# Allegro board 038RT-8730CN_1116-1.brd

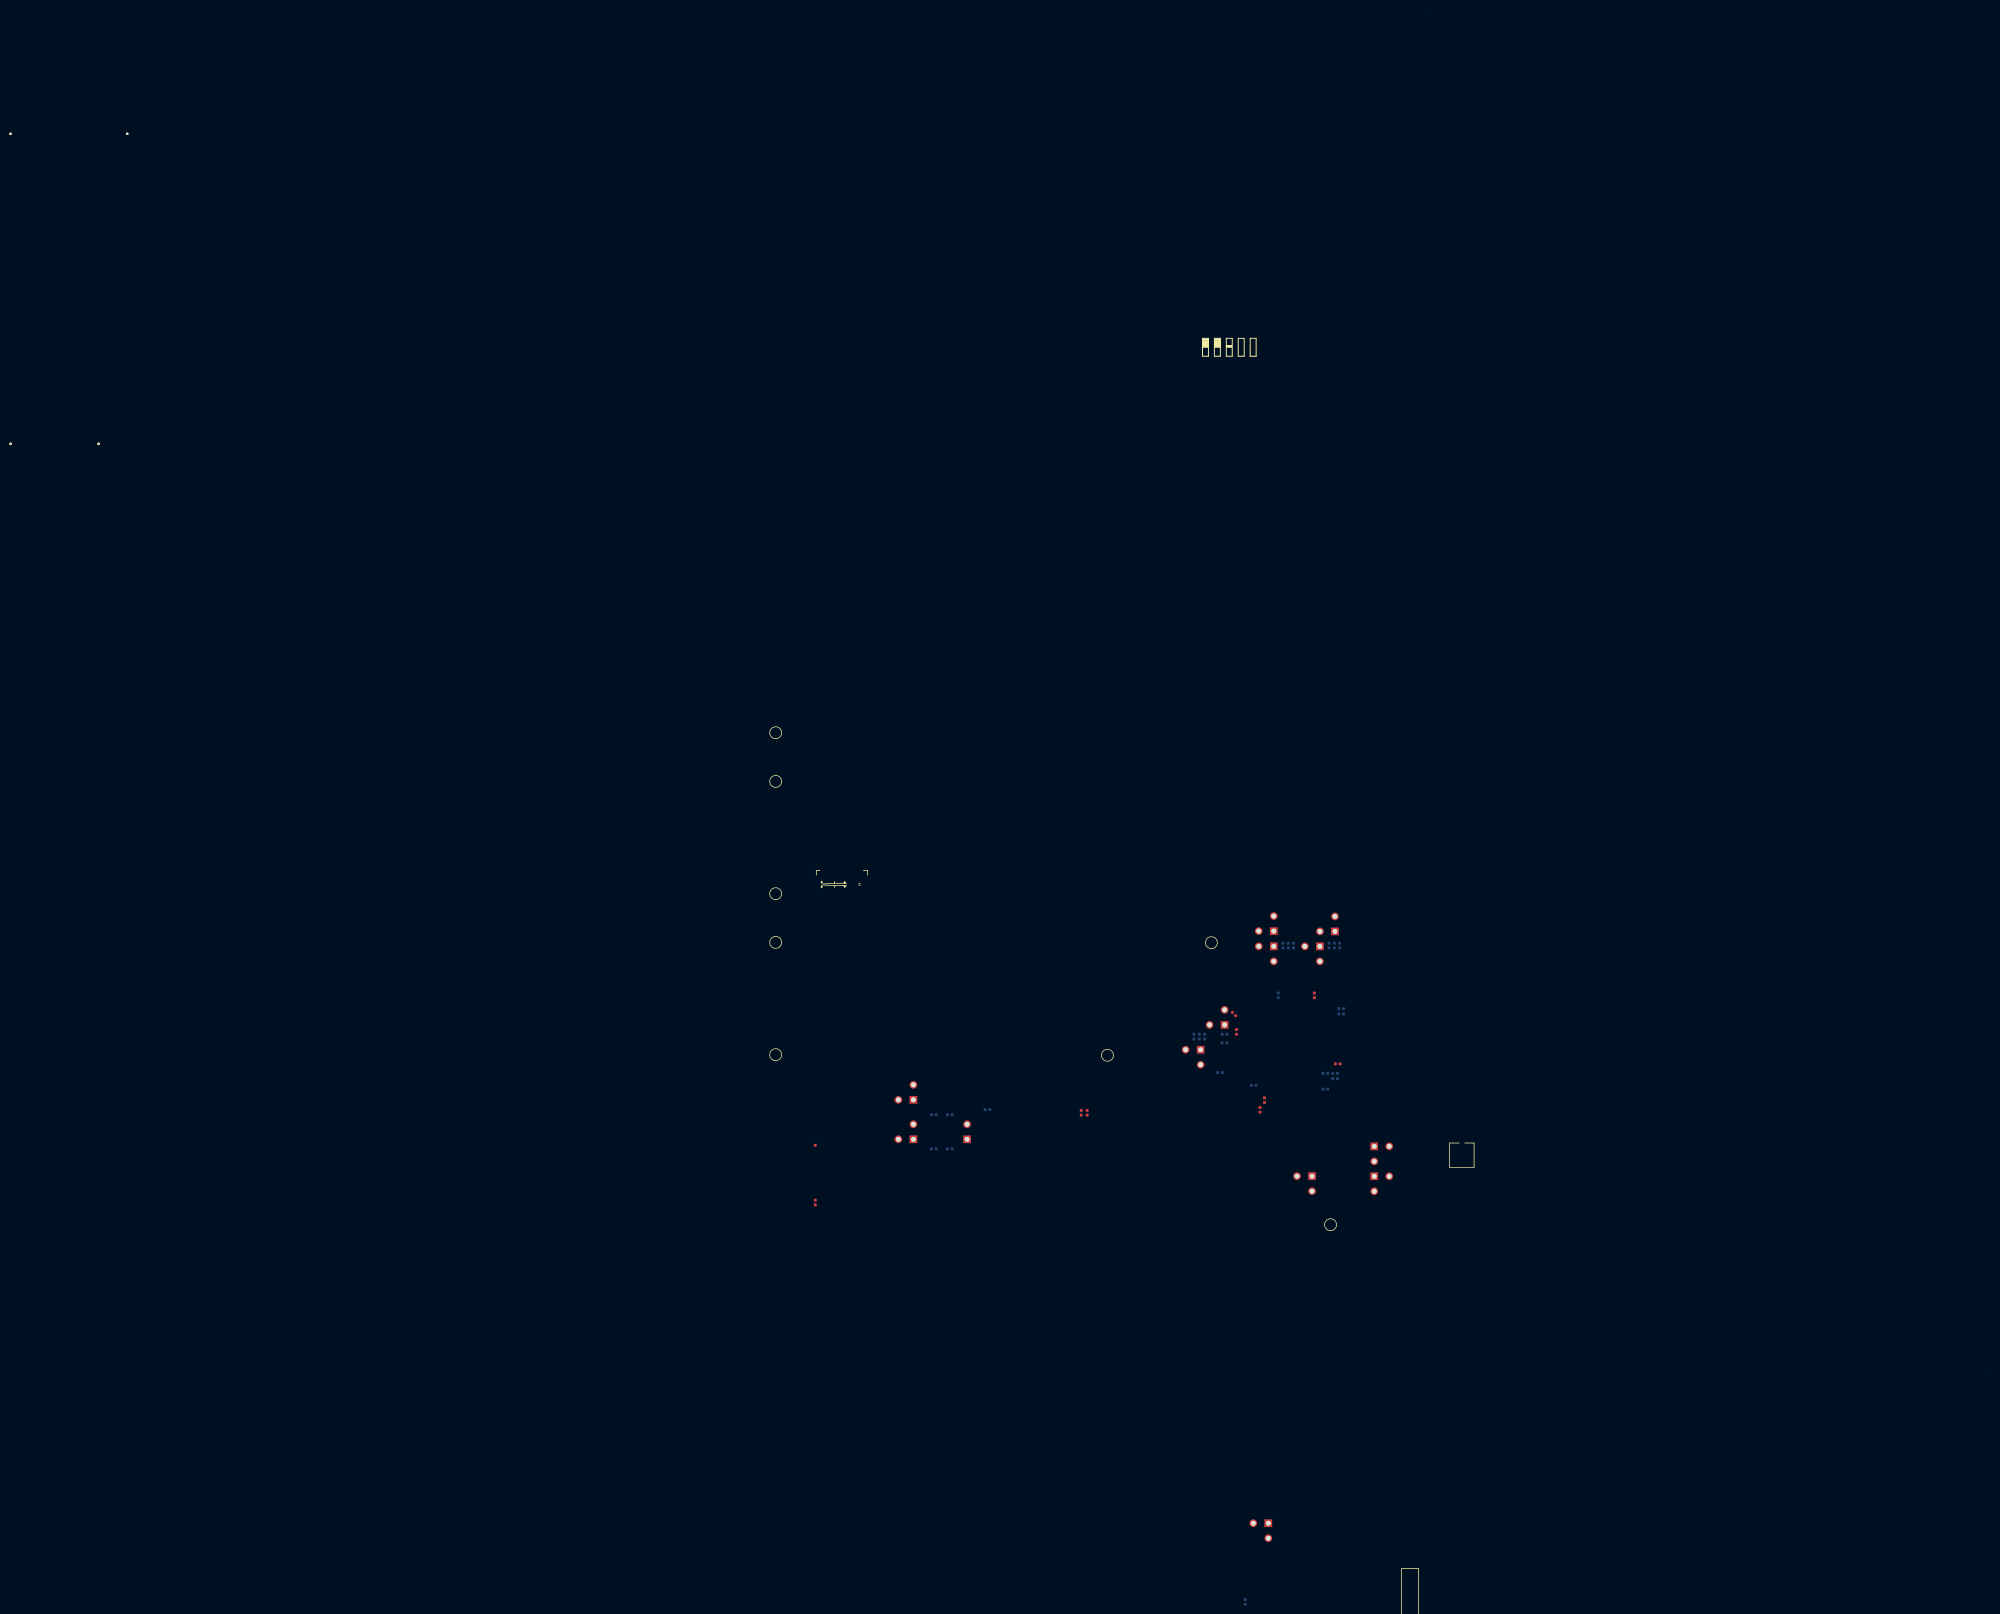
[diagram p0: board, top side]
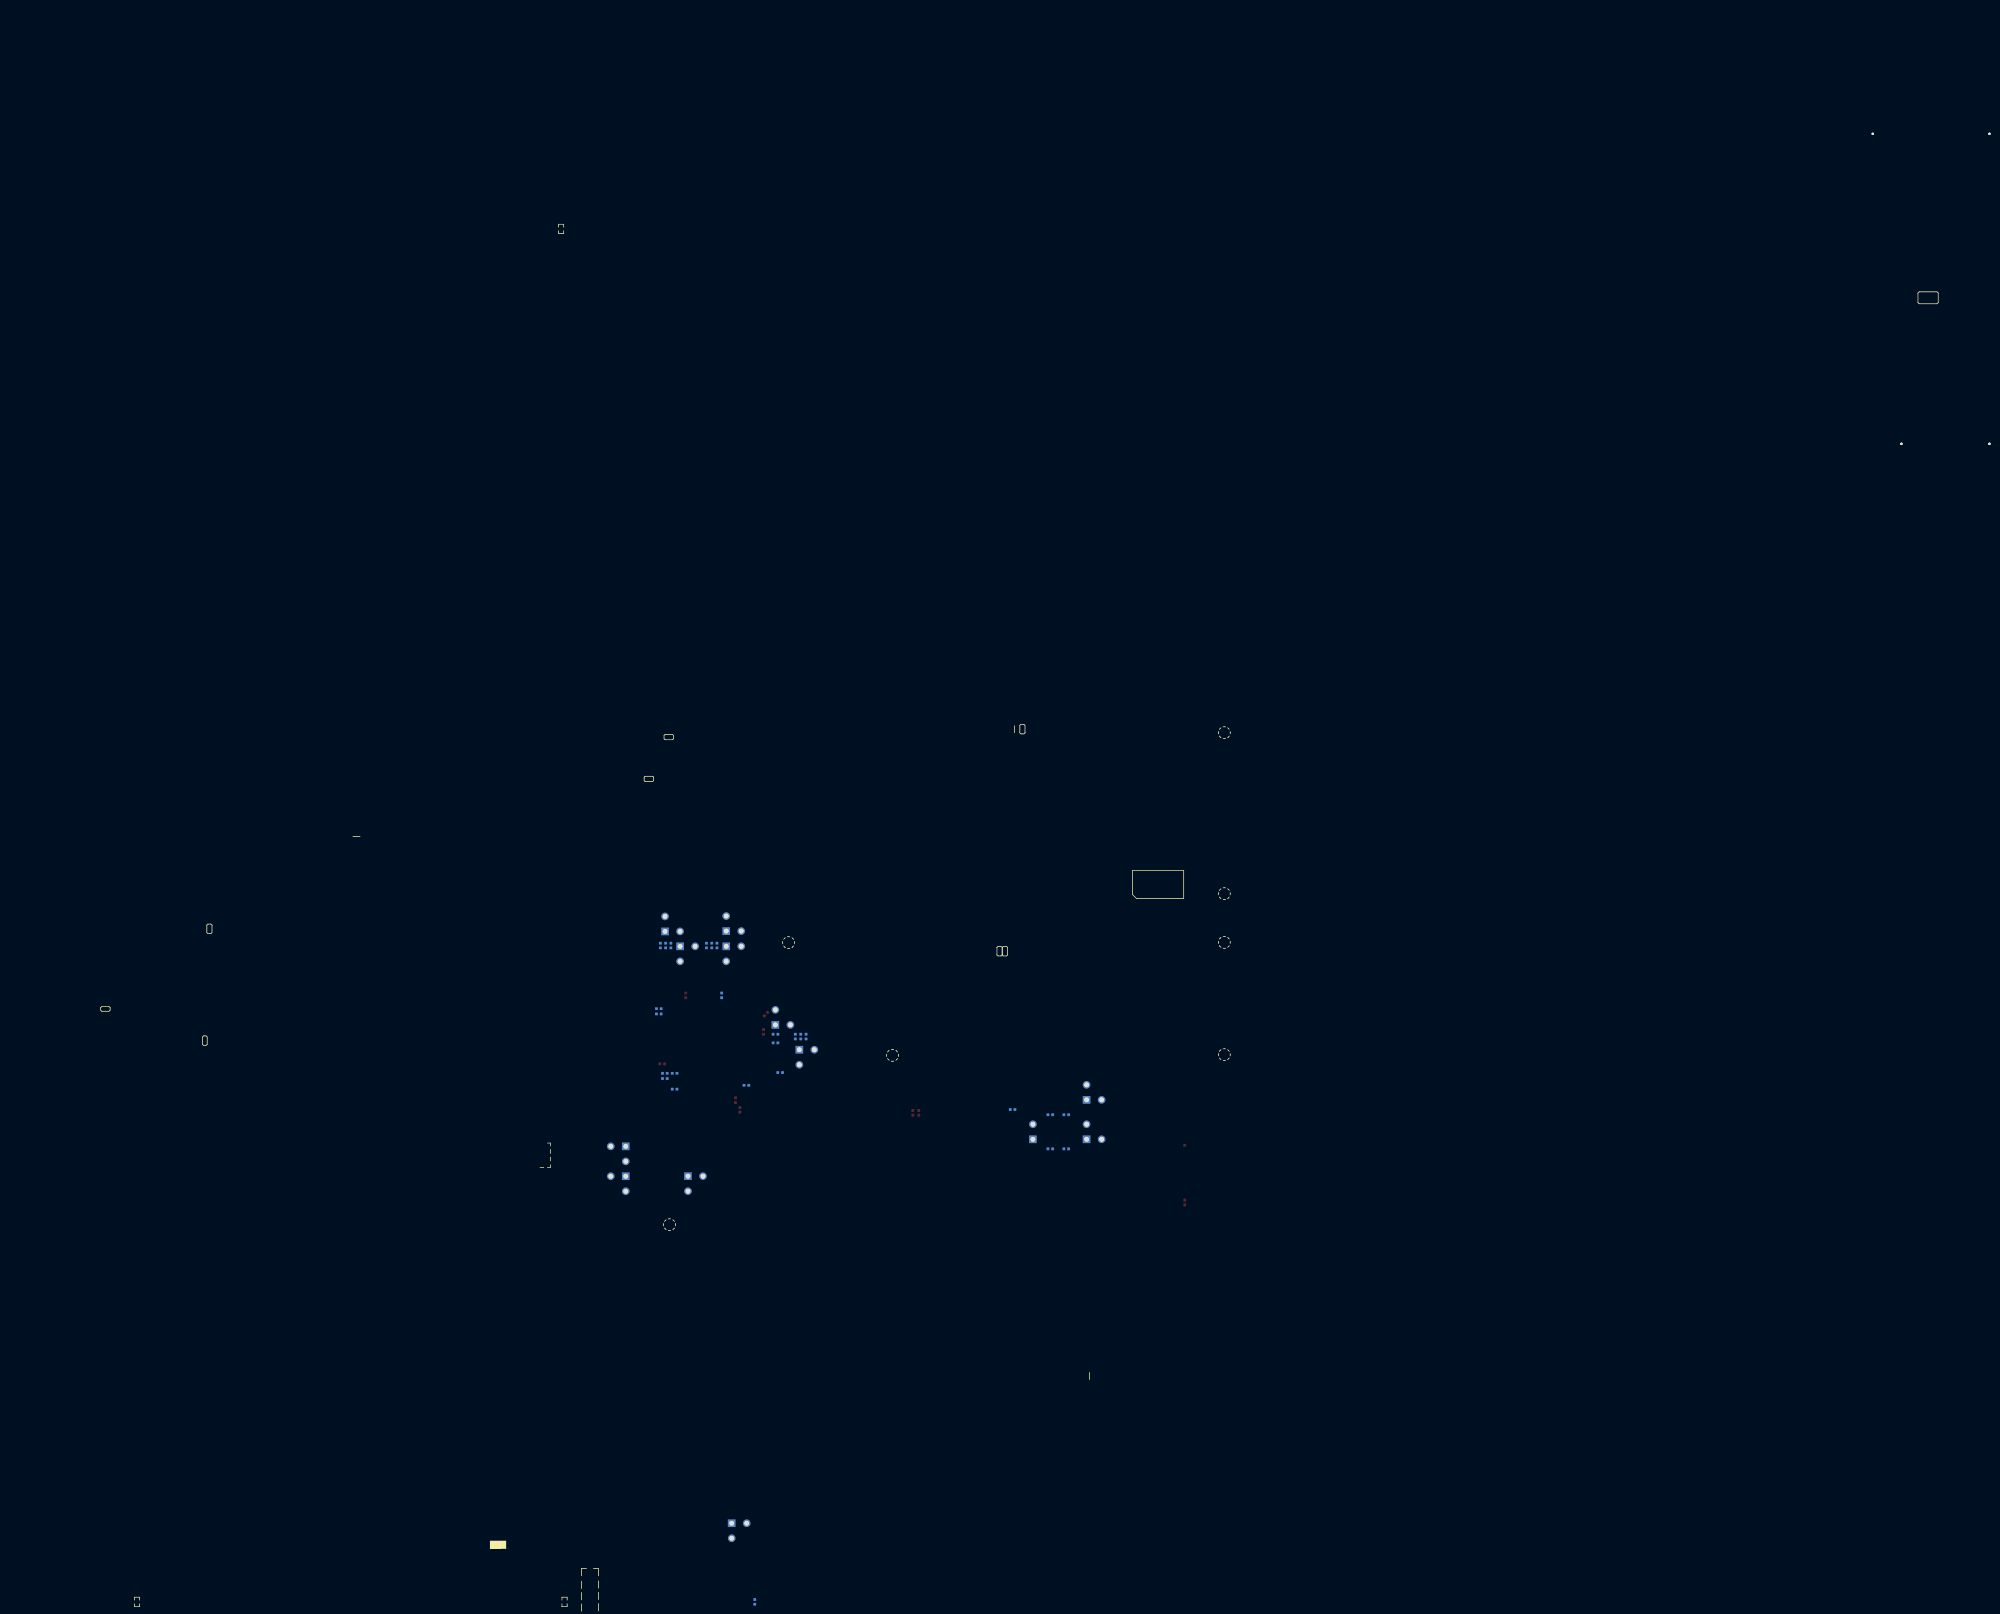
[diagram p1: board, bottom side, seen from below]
No outline. copper layers: Top, Bottom. Coordinates in mm from the lowest, leftmost part position.

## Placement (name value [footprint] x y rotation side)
1BD1  BD120-1.5A-S4-MU  [FB0402]  339.97 257.1 270 bottom
1BD2  BD120-1.5A-S4-MU  [FB0402]  355.74 254.24 180 bottom
1BD3  BD120-1.5A-S4-MU  [FB0402]  338.93 257.1 270 bottom
1BD5  BD120-1.5A-S4-MU  [FB0402]  336.11 247.53 0 bottom
1BD7  BD120-1.5A-S4-MU  [FB0402]  341.01 257.1 270 bottom
1BD9  BD120-1.5A-S4-MU  [FB0402]  359.98 244.31 180 bottom
1BD11  BD120-1.5A-S4-MU  [FB0402]  355.74 253.2 180 bottom
1BD12  BD120-1.5A-S4-MU  [FB0402]  347.85 257.1 270 bottom
1BD13  BD120-1.5A-S4-MU  [FB0402]  336.14 240.68 0 bottom
1BD15  BD120-1.5A-S4-MU  [FB0402]  339.26 236.89 0 bottom
1BD16  BD120-1.5A-S4-MU  [FB0402]  342.57 243.52 180 bottom
1BD17  BD120-1.5A-S4-MU  [FB0402]  342.57 242.48 180 bottom
1BD18  BD120-1.5A-S4-MU  [FB0402]  354.49 239.43 180 bottom
1BD19  BD120-1.5A-S4-MU  [FB0402]  354.49 238.23 180 bottom
1BD20  BD120-1.5A-S4-MU  [FB0402]  334.56 247.48 270 bottom
1BD21  BD120-1.5A-S4-MU  [FB0402]  354.49 236.09 180 bottom
1BD22  BD120-1.5A-S4-MU  [FB0402]  341.08 233.24 180 bottom
1BD23  BD120-1.5A-S4-MU  [FB0402]  341.08 235.3 0 bottom
1BD27  NC/BD120-1.5A-S4-MU  [FB0402]  242.51 266.02 180 bottom
1BD28  BD120-1.5A-S4-MU  [FB0402]  335.59 250.31 270 bottom
1BD29  BD120-1.5A-S4-MU  [FB0402]  345.59 257.1 270 bottom
1BD30  BD120-1.5A-S4-MU  [FB0402]  335.74 253.12 225 bottom
1BD31  BD120-1.5A-S4-MU  [FB0402]  352.63 256.63 180 bottom
1BD32  BD120-1.5A-S4-MU  [FB0402]  265.06 266.44 270 top
1BD33  BD120-1.5A-S4-MU  [FB0402]  339.05 127.89 270 bottom
1BD34  BD120-1.5A-S4-MU  [FB0402]  342.26 231.51 0 bottom
1BD35  BD120-1.5A-S4-MU  [FB0402]  352.4 236.09 180 bottom
1BD36  BD120-1.5A-S4-MU  [FB0402]  334.09 240.69 0 bottom
1BD37  BD120-1.5A-S4-MU  [FB0402]  349.98 257.1 270 bottom
1C1  NC/1P-25-N-S2-WA  [C0201]  347.94 238.42 45 top
1C2  10P-50-N-S2-MU  [C0201]  352.27 233.44 300 top
1C3  NC/1.2P-50-N-S2-MU  [C0201]  349.75 237.46 45 top
1C4  NC/1P-25-N-S2-WA  [C0201]  346.58 238.11 225 top
1C5  NC/1.2P-50-N-S2-MU  [C0201]  347.55 236.29 225 top
1C6  10P-50-N-S2-MU  [C0201]  349.44 232.63 90 top
1C7  NC/10P-50-N-S2-MU  [C0201]  349.14 232.33 180 top
1C8  CNC-S2  [C0201]  349.14 227.46 180 top
1C9  NC/1P-25-N-S2-WA  [C0201]  345.65 237.58 180 bottom
1C10  NC/1.2P-50-N-S2-MU  [C0201]  345.05 235.61 180 bottom
1C11  NC/1P-25-N-S2-WA  [C0201]  343.88 238.23 180 top
1C12  NC/1.2P-50-N-S2-MU  [C0201]  343.28 236.26 180 top
1C13  10P-50-N-S2-MU  [C0201]  343.58 228.62 90 top
1C14  NC/10P-50-N-S2-MU  [C0201]  343.88 228.32 0 top
1C15  CNC-S2  [C0201]  343.88 226.5 0 top
1C16  NC/1P-25-N-S2-WA  [C0201]  343.88 238.23 180 bottom
1C17  NC/0.1U-35-X-S2-MU  [C0201]  352.4 242.06 180 bottom
1C18  NC/0.1U-35-X-S2-MU  [C0201]  352.4 241.21 180 bottom
1C19  NC/1.2P-50-N-S2-MU  [C0201]  343.28 236.26 180 bottom
1C20  0.1U-35-X-S2-MU  [C0201]  352.4 238.98 0 bottom
1C21  0.1U-35-X-S2-MU  [C0201]  352.4 239.83 0 bottom
1C22  0.1U-16-X-S4-MU  [C0402]  262.52 266.41 90 top
1C23  0.9P-50-N-S4-MU  [C0402]  335.37 245.27 270 top
1C24  0.1U-25-X-S4-TY  [C0402]  242.54 267.1 0 bottom
1C25  0.9P-50-N-S4-MU  [C0402]  335.37 242.5 90 top
1C38  1P-50-N-S4-WA  [C0402]  234.52 258.72 0 bottom
1C39  22P-50-N-S4-AVX  [C0402]  231.12 258.72 0 bottom
1C40  1P-50-N-S4-WA  [C0402]  234.52 265.99 0 bottom
1C41  22P-50-N-S4-AVX  [C0402]  231.12 265.99 0 bottom
1C44  0.1U-35-X-S2-MU  [C0201]  342.71 247.36 0 bottom
1C45  0.1U-35-X-S2-MU  [C0201]  351.18 251.27 270 bottom
1C46  0.1U-35-X-S2-MU  [C0201]  342.71 246.51 0 bottom
1C47  0.1U-35-X-S2-MU  [C0201]  351.41 244.05 180 bottom
1C48  0.1U-35-X-S2-MU  [C0201]  338.55 244.6 180 top
1C49  0.1U-35-X-S2-MU  [C0201]  351.41 247.77 180 bottom
1C52  0.1U-35-X-S2-MU  [C0201]  342.71 248.21 0 bottom
1C53  10U-10-X-S4-SS  [C0402]  326.53 248.35 90 bottom
1C54  0.1U-35-X-S2-MU  [C0201]  347.6 251.27 270 bottom
1C55  0.1U-25-X-S4-TY  [C0402]  328.8 248.35 90 bottom
1C56  0.1U-35-X-S2-MU  [C0201]  355.52 245.28 0 top
1C57  NC/10U-10-X-S4-SS  [C0402]  327.66 248.35 90 bottom
1C58  0.1U-35-X-S2-MU  [C0201]  342.44 255.8 90 top
1C59  0.1U-35-X-S2-MU  [C0201]  351.4 249.26 180 bottom
1C60  10U-10-X-S4-SS  [C0402]  357.88 254.29 0 bottom
1C61  0.1U-35-X-S2-MU  [C0201]  346.65 251.26 270 bottom
1C62  22U-25-X-S8-MU  [C0805]  326.41 256.59 0 bottom
1C63  22U-25-X-S8-MU  [C0805]  326.41 258.62 0 bottom
1C64  0.1U-35-X-S2-MU  [C0201]  338.55 242.47 180 top
1C65  47U-16-T-SC  [CODE_C]  259.93 272.36 180 bottom
1C66  10U-16-T-SA  [CODE_A]  259.97 272.36 180 top
1C67  10U-10-X-S4-SS  [C0402]  357.88 253.17 0 bottom
1C68  22U-10-T-SA  [CODE_A]  357.27 210.88 0 bottom
1C69  22U-10-T-SA  [CODE_A]  357.27 213.47 0 bottom
1C70  22U-10-T-SA  [CODE_A]  357.27 216.04 0 bottom
1C71  22U-10-T-SA  [CODE_A]  357.27 213.47 0 top
1C72  22U-10-T-SA  [CODE_A]  357.27 210.88 0 top
1C73  10U-10-X-S4-SS  [C0402]  334.06 239.62 180 bottom
1C74  0.1U-35-X-S2-MU  [C0201]  345.35 242.65 90 bottom
1C75  0.1U-35-X-S2-MU  [C0201]  355.52 242.53 0 top
1C76  10U-10-X-S4-SS  [C0402]  339.23 237.96 180 bottom
1C77  0.1U-35-X-S2-MU  [C0201]  344.54 242.65 90 bottom
1C78  0.1U-35-X-S2-MU  [C0201]  338.55 243.15 180 top
1C79  0.1U-35-X-S2-MU  [C0201]  338.55 241.78 180 top
1C83  10U-10-X-S4-SS  [C0402]  354.52 240.52 0 bottom
1C84  0.1U-35-X-S2-MU  [C0201]  346.87 242.65 90 bottom
1C85  0.1U-35-X-S2-MU  [C0201]  346.14 242.65 90 bottom
1C88  0.1U-35-X-S2-MU  [C0201]  338.55 245.26 180 top
1C89  10U-10-X-S4-SS  [C0402]  333.03 248.85 180 bottom
1C90  10U-10-X-S4-SS  [C0402]  354.52 237.15 0 bottom
1C91  0.1U-35-X-S2-MU  [C0201]  346.46 239.87 0 bottom
1C92  22U-25-X-S8-MU  [C0805]  366.24 212.93 180 bottom
1C93  22U-25-X-S8-MU  [C0805]  366.24 212.93 180 top
1C94  47U-16-T-SC  [CODE_C]  365.79 209.62 180 bottom
1C95  10U-16-T-SA  [CODE_A]  365.79 209.62 180 top
1C96  10U-10-X-S4-SS  [C0402]  356.6 240.52 0 bottom
1C97  10U-10-X-S4-SS  [C0402]  340.61 232.74 270 top
1C98  0.1U-35-X-S2-MU  [C0201]  339.67 233.64 270 top
1C99  10U-10-X-S4-SS  [C0402]  341.55 234.8 270 top
1C100  0.1U-35-X-S2-MU  [C0201]  341.83 237.95 270 top
1C101  10U-10-X-S4-SS  [C0402]  333.03 247.01 180 bottom
1C102  0.1U-35-X-S2-MU  [C0201]  351.41 245.56 180 bottom
1C105  0.1U-35-X-S2-MU  [C0201]  351.4 246.35 180 bottom
1C106  10U-10-X-S4-SS  [C0402]  356.43 267.74 90 bottom
1C107  0.1U-35-X-S2-MU  [C0201]  355.52 246.65 0 top
1C108  0.1U-25-X-S4-TY  [C0402]  355.31 267.74 90 bottom
1C109  NC/10U-10-X-S4-SS  [C0402]  357.55 267.74 90 bottom
1C110  1U-10-X-S4-MU  [C0402]  357.14 242.53 180 top
1C111  10U-10-X-S4-SS  [C0402]  335.59 249.34 270 top
1C112  0.1U-35-X-S2-MU  [C0201]  337.6 250.06 270 top
1C113  10U-25-X-S6-MU  [C0603]  361.74 247.85 90 bottom
1C116  22U-25-X-S8-MU  [C0805]  346.8 259.97 180 bottom
1C117  22U-25-X-S8-MU  [C0805]  346.8 262.13 180 bottom
1C118  10U-10-X-S4-SS  [C0402]  344.5 257.13 90 bottom
1C119  0.1U-35-X-S2-MU  [C0201]  345.72 251.26 270 bottom
1C120  47U-16-T-SC  [CODE_C]  280.47 270.61 270 bottom
1C121  10U-16-T-SA  [CODE_A]  280.47 270.61 270 top
1C122  10U-10-X-S4-SS  [C0402]  356.6 239.41 0 bottom
1C123  10U-10-X-S4-SS  [C0402]  335.05 253.14 135 top
1C124  0.1U-35-X-S2-MU  [C0201]  338.55 251.94 180 top
1C125  10U-10-X-S4-SS  [C0402]  352.16 257.13 90 top
1C126  0.1U-35-X-S2-MU  [C0201]  352.11 255.75 180 top
1C127  10U-10-X-S4-SS  [C0402]  263.79 266.41 90 top
1C128  0.1U-35-X-S2-MU  [C0201]  261.25 266.41 90 top
1C129  10U-10-X-S4-SS  [C0402]  332.04 240.68 180 bottom
1C130  0.1U-25-X-S4-TY  [C0402]  337.96 127.92 90 bottom
1C131  22U-10-T-SA  [CODE_A]  343.5 130.48 0 bottom
1C132  22U-10-T-SA  [CODE_A]  343.5 125.35 0 top
1C133  22U-10-T-SA  [CODE_A]  343.5 127.92 0 top
1C134  22U-10-T-SA  [CODE_A]  343.5 127.92 0 bottom
1C135  22U-10-T-SA  [CODE_A]  343.5 125.35 0 bottom
1C136  10U-10-X-S4-SS  [C0402]  346.61 267.74 90 bottom
1C137  0.1U-25-X-S4-TY  [C0402]  345.5 267.74 90 bottom
1C138  NC/10U-10-X-S4-SS  [C0402]  347.73 267.74 90 bottom
1C139  22U-25-X-S8-MU  [C0805]  335.27 267.42 270 bottom
1C140  47U-16-T-SC  [CODE_C]  285.09 270.61 270 bottom
1C141  10U-16-T-SA  [CODE_A]  285.09 270.61 270 top
1C142  22U-25-X-S8-MU  [C0805]  337.56 267.42 270 bottom
1C143  NC/10P-50-N-S4-WA  [C0402]  355.78 250.66 180 bottom
1C144  NC/10P-50-N-S4-WA  [C0402]  355.78 249.49 180 bottom
1C145  NC/10P-50-N-S4-WA  [C0402]  205.88 251.35 90 top
1C146  NC/10P-50-N-S4-WA  [C0402]  205.88 254.55 90 top
1C147  NC/10P-50-N-S4-WA  [C0402]  205.88 244.08 90 top
1C148  NC/10P-50-N-S4-WA  [C0402]  205.88 247.28 90 top
1C149  NC/10P-50-N-S4-WA  [C0402]  205.88 259.98 90 top
1C150  NC/10P-50-N-S4-WA  [C0402]  205.88 263.18 90 top
1C152  0.1U-35-X-S2-MU  [C0201]  348.44 251.27 270 bottom
1C153  CNC-S2  [C0201]  350.9 247.1 180 bottom
1D1  RCLAMP3321P-SLP1006P2  [DIODE_1X0P6MM]  352.51 232.17 30 top
1D2  RCLAMP3321P-SLP1006P2  [DIODE_1X0P6MM]  349.02 228.35 0 top
1D3  RCLAMP3321P-SLP1006P2  [DIODE_1X0P6MM]  344 227.38 180 top
1J1  HDR-4X1-F-1  [CONN_4X1_2P54MM_FL10P5MM]  213.31 267.71 270 top
1J2  HDR-4X1-F-1  [CONN_4X1_2P54MM_FL10P5MM]  332.56 125.38 270 top
1J3  HDR-4X1-F-1  [CONN_4X1_2P54MM_FL10P5MM]  207.08 267.71 270 top
1J4  HDR-8X1-M  [JP_8P_100]  216.58 178.6 270 top
1J5  HDR-1X1-M  [JP_1P_RD070_040]  347.48 133.26 90 top
1J6  HDR-2X1-M  [JP_2P_100]  344.57 133.26 90 top
1J7  HDR-2X1-M  [JP_2P_100]  321.46 157.26 0 top
1J8  HDR-2X1-M  [JP_2P_100]  317.65 157.26 0 top
1J9  HDR-2X1-M  [JP_2P_100]  325.27 157.26 0 top
1K1  CU/UA2-12NJ-A-V2  [RL_NECUA2_12V_V2]  272.11 262.91 0 bottom
1K2  CU/UA2-12NJ-A-V2  [RL_NECUA2_12V_V2]  272.11 255.9 0 bottom
1K3  CU/UA2-12NJ-A-V2  [RL_NECUA2_12V_V2]  272.11 248.89 0 bottom
1K4  CU/UA2-12NJ-A-V2  [RL_NECUA2_12V_V2]  223.19 270.76 0 bottom
1K5  CU/UA2-12NJ-A-V2  [RL_NECUA2_12V_V2]  364.28 270.8 270 bottom
1K6  CU/UA2-12NJ-A-V2  [RL_NECUA2_12V_V2]  341.27 141.08 90 bottom
1K7  CU/UA2-12NJ-A-V2  [RL_NECUA2_12V_V2]  272.41 272.41 270 bottom
1K8  CU/UA2-12NJ-A-V2  [RL_NECUA2_12V_V2]  223.19 262.36 0 bottom
1K9  CU/UA2-12NJ-A-V2  [RL_NECUA2_12V_V2]  368.52 223.36 180 bottom
1K10  CU/UA2-12NJ-A-V2  [RL_NECUA2_12V_V2]  249.02 253.72 0 bottom
1K11  CU/UA2-12NJ-A-V2  [RL_NECUA2_12V_V2]  223.19 246.46 0 bottom
1K12  CU/UA2-12NJ-A-V2  [RL_NECUA2_12V_V2]  234.62 253.72 0 bottom
1K13  CU/UA2-12NJ-A-V2  [RL_NECUA2_12V_V2]  223.19 253.72 0 bottom
1K14  CU/UA2-12NJ-A-V2  [RL_NECUA2_12V_V2]  249.02 246.46 0 bottom
1K15  CU/UA2-12NJ-A-V2  [RL_NECUA2_12V_V2]  234.62 246.46 0 bottom
1K16  CU/UA2-12NJ-A-V2  [RL_NECUA2_12V_V2]  246.05 270.76 0 bottom
1K18  CU/UA2-12NJ-A-V2  [RL_NECUA2_12V_V2]  246.05 262.36 0 bottom
1K19  CU/UA2-12NJ-A-V2  [RL_NECUA2_12V_V2]  234.62 262.36 0 bottom
1K20  CU/UA2-12NJ-A-V2  [RL_NECUA2_12V_V2]  341.93 263.97 90 bottom
1K21  CU/UA2-12NJ-A-V2  [RL_NECUA2_12V_V2]  329.46 252.44 0 bottom
1K22  CU/UA2-12NJ-A-V2  [RL_NECUA2_12V_V2]  326.35 241.95 90 bottom
1K23  CU/UA2-12NJ-A-V2  [RL_NECUA2_12V_V2]  350.07 215.01 90 bottom
1K25  CU/UA2-12NJ-A-V2  [RL_NECUA2_12V_V2]  339.93 272.42 0 bottom
1K26  CU/UA2-12NJ-A-V2  [RL_NECUA2_12V_V2]  368.52 217 180 bottom
1K28  CU/UA2-12NJ-A-V2  [RL_NECUA2_12V_V2]  352.96 272.35 0 bottom
1K29  CU/UA2-12NJ-A-V2  [RL_NECUA2_12V_V2]  351.74 263.97 90 bottom
1K30  CU/UA2-12NJ-A-V2  [RL_NECUA2_12V_V2]  202.41 270.96 270 bottom
1K31  CU/UA2-12NJ-A-V2  [RL_NECUA2_12V_V2]  202.41 259.53 270 bottom
1K32  CU/UA2-12NJ-A-V2  [RL_NECUA2_12V_V2]  202.41 248.1 270 bottom
1K34  CU/UA2-12NJ-A-V2  [RL_NECUA2_12V_V2]  211.76 253.72 0 bottom
1K35  CU/UA2-12NJ-A-V2  [RL_NECUA2_12V_V2]  211.76 246.46 0 bottom
1K36  CU/UA2-12NJ-A-V2  [RL_NECUA2_12V_V2]  211.76 262.36 0 bottom
1K39  CU/UA2-12NJ-A-V2  [RL_NECUA2_12V_V2]  334.31 141.08 90 bottom
1L1  L2.2U-1.15A-S2.0X1.6-CT  [IND_201610]  330.75 247.9 270 bottom
1L3  L2.2U-1.15A-S2.0X1.6-CT  [IND_201610]  356.06 265.2 90 bottom
1L4  L2.2U-1.15A-S2.0X1.6-CT  [IND_201610]  346.25 265.2 90 bottom
1R1  0-5-S2  [R0201]  348.84 237.94 315 top
1R2  0-5-S2  [R0201]  347.06 237.2 315 top
1R3  0-5-S2  [R0201]  349.44 233.91 270 top
1R4  NC/0-5-S2  [R0201]  349.14 234.21 0 top
1R5  0-5-S2  [R0201]  345.35 236.59 270 bottom
1R6  0-5-S2  [R0201]  343.58 237.25 270 top
1R7  0-5-S2  [R0201]  343.58 229.9 270 top
1R8  NC/0-5-S2  [R0201]  343.88 230.2 180 top
1R9  0-5-S2  [R0201]  343.58 237.25 270 bottom
1R10  0-5-S4  [R0402]  262.37 246.99 90 top
1R11  0-5-S4  [R0402]  261.1 246.99 90 top
1R12  NC/10K-1-S4  [R0402]  258.46 266.41 90 top
1R13  0-5-S4  [R0402]  259.73 266.41 90 top
1R14  NC/10K-1-S4  [R0402]  259.83 246.99 90 top
1R15  0-5-S4  [R0402]  257.19 266.41 90 top
1R16  0-5-S4  [R0402]  258.56 246.99 90 top
1R17  0-5-S4  [R0402]  255.92 266.41 90 top
1R18  NC/10K-1-S4  [R0402]  257.44 246.99 90 top
1R19  0-5-S4  [R0402]  215.75 267.71 180 bottom
1R20  0-5-S4  [R0402]  215.75 272.79 180 bottom
1R21  0-5-S4  [R0402]  215.75 275.33 180 bottom
1R22  45.3-1-S4  [R0402]  359.07 272.79 90 bottom
1R23  45.3-1-S4  [R0402]  267.21 274.41 90 bottom
1R24  0-5-S4  [R0402]  335.15 125.4 180 bottom
1R25  45.3-1-S4  [R0402]  359.07 268.8 270 bottom
1R26  45.3-1-S4  [R0402]  267.21 270.42 270 bottom
1R27  0-5-S4  [R0402]  335.15 130.48 180 bottom
1R28  0-5-S4  [R0402]  335.15 133.02 180 bottom
1R29  NC/45.3-1-S4  [R0402]  245.33 266.52 90 bottom
1R30  0-5-S4  [R0402]  209.52 267.71 180 bottom
1R31  0-5-S4  [R0402]  209.52 272.79 180 bottom
1R32  0-5-S4  [R0402]  209.52 275.33 180 bottom
1R33  NC/45.3-1-S4  [R0402]  244.18 266.52 270 bottom
1R34  10K-1-S4  [R0402]  216.58 176.06 270 bottom
1R35  10K-1-S4  [R0402]  219.12 176.06 270 bottom
1R36  10K-1-S4  [R0402]  221.66 176.06 270 bottom
1R37  10K-1-S4  [R0402]  224.2 176.06 270 bottom
1R38  0-5-S4  [R0402]  219 165.9 0 bottom
1R39  10K-1-S4  [R0402]  226.74 176.06 270 bottom
1R40  10K-1-S4  [R0402]  229.28 176.06 270 bottom
1R41  10K-1-S4  [R0402]  231.82 176.06 270 bottom
1R42  0-5-S4  [R0402]  231.95 165.9 180 bottom
1R43  12K-1-S4  [R0402]  360.01 247.6 0 bottom
1R45  32.4-1-S4  [R0402]  242.78 252.51 90 bottom
1R47  32.4-1-S4  [R0402]  242.78 245.25 90 bottom
1R48  0-5-S4  [R0402]  322.74 238.45 90 bottom
1R49  NC/0-5-S4  [R0402]  329.96 238.45 90 bottom
1R50  0-5-S4  [R0402]  362.43 216.24 270 top
1R51  NC/0-5-S4  [R0402]  333.58 271.32 270 bottom
1R53  0-5-S4  [R0402]  346.61 274.45 90 bottom
1R54  NC/0-5-S4  [R0402]  346.61 270.25 270 bottom
1R55  0-5-S4  [R0402]  335.43 276.09 180 bottom
1R57  NC/10K-1-S4  [R0402]  221.89 267.13 0 bottom
1R58  NC/10K-1-S4  [R0402]  221.89 274.39 0 bottom
1R59  NC/10K-1-S4  [R0402]  221.89 258.72 0 bottom
1R60  NC/10K-1-S4  [R0402]  221.89 265.99 0 bottom
1R61  0-5-S4  [R0402]  320.75 124.98 0 bottom
1R62  0-5-S4  [R0402]  323.75 124.98 180 bottom
1R63  0-5-S4  [R0402]  240.45 245.25 90 bottom
1R64  0-5-S4  [R0402]  241.62 245.25 90 bottom
1R65  0-5-S4  [R0402]  241.62 247.67 270 bottom
1R66  0-5-S4  [R0402]  240.45 247.67 270 bottom
1R67  0-5-S4  [R0402]  240.45 252.51 90 bottom
1R68  0-5-S4  [R0402]  241.62 252.51 90 bottom
1R69  0-5-S4  [R0402]  241.62 254.93 270 bottom
1R70  0-5-S4  [R0402]  240.45 254.93 270 bottom
1R71  2-5-D-2  [RC02W_27MM]  185.96 272.76 180 bottom
1R72  2-5-D-2  [RC02W_27MM]  185.96 261.33 180 bottom
1R73  2-5-D-2  [RC02W_27MM]  185.96 249.9 180 bottom
1R74  0-5-S4  [R0402]  242.78 247.67 270 bottom
1R75  0-5-S4  [R0402]  242.78 254.93 270 bottom
1R76  0-5-S4  [R0402]  360.01 243.24 180 bottom
1R77  0-5-S4  [R0402]  355.77 252.13 180 bottom
1R78  0-5-S4  [R0402]  348.92 257.13 270 bottom
1R79  0-5-S4  [R0402]  343.37 257.13 270 bottom
1R81  0-5-S4  [R0402]  360.01 245.38 180 bottom
1R82  0-5-S4  [R0402]  360.01 248.7 180 bottom
1R83  0-5-S4  [R0402]  360.01 246.5 180 bottom
1SMP1  MINI-SMP-18S107-40ML5-V2  [CONN_SMP_18S107]  354.76 229.13 210 top
1SMP2  MINI-SMP-18S107-40ML5-V2  [CONN_SMP_18S107]  349.44 224.03 180 top
1SMP3  MINI-SMP-18S107-40ML5-V2  [CONN_SMP_18S107]  343.58 223.07 180 top
1ST3  SHORT  [DEFAULT_SHORT_SMALL]  347.6 252.43 180 top
1ST4  SHORT  [DEFAULT_SHORT_SMALL]  354.32 220.59 0 top
1ST5  SHORT  [DEFAULT_SHORT_SMALL]  354.32 219.83 0 top
1ST8  SHORT  [DEFAULT_SHORT_SMALL]  372.31 207.85 90 bottom
1ST11  SHORT  [DEFAULT_SHORT_SMALL]  353.34 276.71 270 top
1ST12  SHORT  [DEFAULT_SHORT_SMALL]  345.11 272.16 270 bottom
1ST13  SHORT  [DEFAULT_SHORT_SMALL]  322.74 240.69 270 bottom
1ST14  SHORT  [DEFAULT_SHORT_SMALL]  336.63 277.12 0 bottom
1ST15  SHORT  [DEFAULT_SHORT_SMALL]  361.74 244.4 270 bottom
1ST16  SHORT  [DEFAULT_SHORT_SMALL]  347.58 253.42 180 top
1ST17  SHORT  [DEFAULT_SHORT_SMALL]  346.07 272.08 270 bottom
1ST18  SHORT  [DEFAULT_SHORT_SMALL]  373.1 207.65 90 bottom
1ST19  SHORT  [DEFAULT_SHORT_SMALL]  354.51 276.71 270 top
1SW5  SW-SLIDE-8-D2.54-TRI-ECE  [SW_DIPX8P_2P54_MM_V2]  225.47 169.71 0 top
1SW6  SW-SLIDE-4-D2.54-TRI-ECE  [SW_DIPX4P_2P54MM_ETD]  322.25 128.79 0 top
1U1  RFASWA358ATF0G  [RF_SW_GW2159_6P]  347.66 233.75 270 top
1U2  RFASWA358ATF0G  [RF_SW_GW2159_6P]  345.36 229.74 270 top
1U3  MX25L25645GM2I-08G/SK-SO8-1.27  [SK_SO8_1P27MM_LOTES]  260.46 255.96 180 bottom
1Y1  XTAL40M-S2016-TAI-12P  [XTAL_2X1P6MM_4P_0P8MM]  333 243.89 45 top
2BD1  BD120-1.5A-S4-MU  [FB0402]  379.97 257.1 270 bottom
2BD2  BD120-1.5A-S4-MU  [FB0402]  395.74 254.24 180 bottom
2BD3  BD120-1.5A-S4-MU  [FB0402]  378.93 257.1 270 bottom
2BD5  BD120-1.5A-S4-MU  [FB0402]  376.11 247.53 0 bottom
2BD7  BD120-1.5A-S4-MU  [FB0402]  381.01 257.1 270 bottom
2BD9  BD120-1.5A-S4-MU  [FB0402]  399.98 244.31 180 bottom
2BD11  BD120-1.5A-S4-MU  [FB0402]  395.74 253.2 180 bottom
2BD12  BD120-1.5A-S4-MU  [FB0402]  387.85 257.1 270 bottom
2BD13  BD120-1.5A-S4-MU  [FB0402]  376.14 240.68 0 bottom
2BD15  BD120-1.5A-S4-MU  [FB0402]  379.26 236.89 0 bottom
2BD16  BD120-1.5A-S4-MU  [FB0402]  382.57 243.52 180 bottom
2BD17  BD120-1.5A-S4-MU  [FB0402]  382.57 242.48 180 bottom
2BD18  BD120-1.5A-S4-MU  [FB0402]  394.49 239.43 180 bottom
2BD19  BD120-1.5A-S4-MU  [FB0402]  394.49 238.23 180 bottom
2BD20  BD120-1.5A-S4-MU  [FB0402]  374.56 247.48 270 bottom
2BD21  BD120-1.5A-S4-MU  [FB0402]  394.49 236.09 180 bottom
2BD22  BD120-1.5A-S4-MU  [FB0402]  381.08 233.24 180 bottom
2BD23  BD120-1.5A-S4-MU  [FB0402]  381.08 235.3 0 bottom
2BD27  NC/BD120-1.5A-S4-MU  [FB0402]  491.65 253.41 0 bottom
2BD28  BD120-1.5A-S4-MU  [FB0402]  375.59 250.31 270 bottom
2BD29  BD120-1.5A-S4-MU  [FB0402]  385.59 257.1 270 bottom
2BD30  BD120-1.5A-S4-MU  [FB0402]  375.74 253.12 225 bottom
2BD31  BD120-1.5A-S4-MU  [FB0402]  392.63 256.63 180 bottom
2BD32  BD120-1.5A-S4-MU  [FB0402]  469.1 252.99 90 top
2BD33  BD120-1.5A-S4-MU  [FB0402]  430.08 127.89 270 bottom
2BD34  BD120-1.5A-S4-MU  [FB0402]  382.26 231.51 0 bottom
2BD35  BD120-1.5A-S4-MU  [FB0402]  392.4 236.09 180 bottom
2BD36  BD120-1.5A-S4-MU  [FB0402]  374.09 240.69 0 bottom
2BD37  BD120-1.5A-S4-MU  [FB0402]  389.98 257.1 270 bottom
2C1  NC/1P-25-N-S2-WA  [C0201]  387.94 238.42 45 top
2C2  10P-50-N-S2-MU  [C0201]  392.27 233.44 300 top
2C3  NC/1.2P-50-N-S2-MU  [C0201]  389.75 237.46 45 top
2C4  NC/1P-25-N-S2-WA  [C0201]  386.58 238.11 225 top
2C5  NC/1.2P-50-N-S2-MU  [C0201]  387.55 236.29 225 top
2C6  10P-50-N-S2-MU  [C0201]  389.44 232.63 90 top
2C7  NC/10P-50-N-S2-MU  [C0201]  389.14 232.33 180 top
2C8  CNC-S2  [C0201]  389.14 227.46 180 top
2C9  NC/1P-25-N-S2-WA  [C0201]  385.65 237.58 180 bottom
2C10  NC/1.2P-50-N-S2-MU  [C0201]  385.05 235.61 180 bottom
2C11  NC/1P-25-N-S2-WA  [C0201]  383.88 238.23 180 top
2C12  NC/1.2P-50-N-S2-MU  [C0201]  383.28 236.26 180 top
2C13  10P-50-N-S2-MU  [C0201]  383.58 228.62 90 top
2C14  NC/10P-50-N-S2-MU  [C0201]  383.88 228.32 0 top
2C15  CNC-S2  [C0201]  383.88 226.5 0 top
2C16  NC/1P-25-N-S2-WA  [C0201]  383.88 238.23 180 bottom
2C17  NC/0.1U-35-X-S2-MU  [C0201]  392.4 242.06 180 bottom
2C18  NC/0.1U-35-X-S2-MU  [C0201]  392.4 241.21 180 bottom
2C19  NC/1.2P-50-N-S2-MU  [C0201]  383.28 236.26 180 bottom
2C20  0.1U-35-X-S2-MU  [C0201]  392.4 238.98 0 bottom
2C21  0.1U-35-X-S2-MU  [C0201]  392.4 239.83 0 bottom
2C22  0.1U-16-X-S4-MU  [C0402]  471.64 253.02 270 top
2C23  0.9P-50-N-S4-MU  [C0402]  375.37 245.27 270 top
2C24  0.1U-25-X-S4-TY  [C0402]  491.61 252.33 180 bottom
2C25  0.9P-50-N-S4-MU  [C0402]  375.37 242.5 90 top
2C38  1P-50-N-S4-WA  [C0402]  499.64 260.71 180 bottom
2C39  22P-50-N-S4-AVX  [C0402]  503.04 260.71 180 bottom
2C40  1P-50-N-S4-WA  [C0402]  499.64 253.44 180 bottom
2C41  22P-50-N-S4-AVX  [C0402]  503.04 253.44 180 bottom
2C44  0.1U-35-X-S2-MU  [C0201]  382.71 247.36 0 bottom
2C45  0.1U-35-X-S2-MU  [C0201]  391.18 251.27 270 bottom
2C46  0.1U-35-X-S2-MU  [C0201]  382.71 246.51 0 bottom
2C47  0.1U-35-X-S2-MU  [C0201]  391.41 244.05 180 bottom
2C48  0.1U-35-X-S2-MU  [C0201]  378.55 244.6 180 top
2C49  0.1U-35-X-S2-MU  [C0201]  391.41 247.77 180 bottom
2C52  0.1U-35-X-S2-MU  [C0201]  382.71 248.21 0 bottom
2C53  10U-10-X-S4-SS  [C0402]  366.53 248.35 90 bottom
2C54  0.1U-35-X-S2-MU  [C0201]  387.6 251.27 270 bottom
2C55  0.1U-25-X-S4-TY  [C0402]  368.8 248.35 90 bottom
2C56  0.1U-35-X-S2-MU  [C0201]  395.52 245.28 0 top
2C57  NC/10U-10-X-S4-SS  [C0402]  367.66 248.35 90 bottom
2C58  0.1U-35-X-S2-MU  [C0201]  382.44 255.8 90 top
2C59  0.1U-35-X-S2-MU  [C0201]  391.4 249.26 180 bottom
2C60  10U-10-X-S4-SS  [C0402]  397.88 254.29 0 bottom
2C61  0.1U-35-X-S2-MU  [C0201]  386.65 251.26 270 bottom
2C62  22U-25-X-S8-MU  [C0805]  366.41 256.59 0 bottom
2C63  22U-25-X-S8-MU  [C0805]  366.41 258.62 0 bottom
2C64  0.1U-35-X-S2-MU  [C0201]  378.55 242.47 180 top
2C65  47U-16-T-SC  [CODE_C]  474.22 247.07 0 bottom
2C66  10U-16-T-SA  [CODE_A]  474.19 247.07 0 top
2C67  10U-10-X-S4-SS  [C0402]  397.88 253.17 0 bottom
2C68  22U-10-T-SA  [CODE_A]  397.27 210.88 0 bottom
2C69  22U-10-T-SA  [CODE_A]  397.27 213.47 0 bottom
2C70  22U-10-T-SA  [CODE_A]  397.27 216.04 0 bottom
2C71  22U-10-T-SA  [CODE_A]  397.27 213.47 0 top
2C72  22U-10-T-SA  [CODE_A]  397.27 210.88 0 top
2C73  10U-10-X-S4-SS  [C0402]  374.06 239.62 180 bottom
2C74  0.1U-35-X-S2-MU  [C0201]  385.35 242.65 90 bottom
2C75  0.1U-35-X-S2-MU  [C0201]  395.52 242.53 0 top
2C76  10U-10-X-S4-SS  [C0402]  379.23 237.96 180 bottom
2C77  0.1U-35-X-S2-MU  [C0201]  384.54 242.65 90 bottom
2C78  0.1U-35-X-S2-MU  [C0201]  378.55 243.15 180 top
2C79  0.1U-35-X-S2-MU  [C0201]  378.55 241.78 180 top
2C83  10U-10-X-S4-SS  [C0402]  394.52 240.52 0 bottom
2C84  0.1U-35-X-S2-MU  [C0201]  386.87 242.65 90 bottom
2C85  0.1U-35-X-S2-MU  [C0201]  386.14 242.65 90 bottom
2C88  0.1U-35-X-S2-MU  [C0201]  378.55 245.26 180 top
2C89  10U-10-X-S4-SS  [C0402]  373.03 248.85 180 bottom
2C90  10U-10-X-S4-SS  [C0402]  394.52 237.15 0 bottom
2C91  0.1U-35-X-S2-MU  [C0201]  386.46 239.87 0 bottom
2C92  22U-25-X-S8-MU  [C0805]  405.1 212.93 180 bottom
2C93  22U-25-X-S8-MU  [C0805]  405.1 212.93 180 top
2C94  47U-16-T-SC  [CODE_C]  404.4 209.62 180 bottom
2C95  10U-16-T-SA  [CODE_A]  404.4 209.62 180 top
2C96  10U-10-X-S4-SS  [C0402]  396.6 240.52 0 bottom
2C97  10U-10-X-S4-SS  [C0402]  380.61 232.74 270 top
2C98  0.1U-35-X-S2-MU  [C0201]  379.67 233.64 270 top
2C99  10U-10-X-S4-SS  [C0402]  381.55 234.8 270 top
2C100  0.1U-35-X-S2-MU  [C0201]  381.83 237.95 270 top
2C101  10U-10-X-S4-SS  [C0402]  373.03 247.01 180 bottom
2C102  0.1U-35-X-S2-MU  [C0201]  391.41 245.56 180 bottom
2C105  0.1U-35-X-S2-MU  [C0201]  391.4 246.35 180 bottom
2C106  10U-10-X-S4-SS  [C0402]  396.43 267.74 90 bottom
2C107  0.1U-35-X-S2-MU  [C0201]  395.52 246.65 0 top
2C108  0.1U-25-X-S4-TY  [C0402]  395.31 267.74 90 bottom
2C109  NC/10U-10-X-S4-SS  [C0402]  397.55 267.74 90 bottom
2C110  1U-10-X-S4-MU  [C0402]  397.14 242.53 180 top
2C111  10U-10-X-S4-SS  [C0402]  375.59 249.34 270 top
2C112  0.1U-35-X-S2-MU  [C0201]  377.6 250.06 270 top
2C113  10U-25-X-S6-MU  [C0603]  401.74 247.85 90 bottom
2C116  22U-25-X-S8-MU  [C0805]  386.8 259.97 180 bottom
2C117  22U-25-X-S8-MU  [C0805]  386.8 262.13 180 bottom
2C118  10U-10-X-S4-SS  [C0402]  384.5 257.13 90 bottom
2C119  0.1U-35-X-S2-MU  [C0201]  385.72 251.26 270 bottom
2C120  47U-16-T-SC  [CODE_C]  452.3 270.23 270 bottom
2C121  10U-16-T-SA  [CODE_A]  452.3 270.23 270 top
2C122  10U-10-X-S4-SS  [C0402]  396.6 239.41 0 bottom
2C123  10U-10-X-S4-SS  [C0402]  375.05 253.14 135 top
2C124  0.1U-35-X-S2-MU  [C0201]  378.55 251.94 180 top
2C125  10U-10-X-S4-SS  [C0402]  392.16 257.13 90 top
2C126  0.1U-35-X-S2-MU  [C0201]  392.11 255.75 180 top
2C127  10U-10-X-S4-SS  [C0402]  470.37 253.02 270 top
2C128  0.1U-35-X-S2-MU  [C0201]  472.91 253.02 270 top
2C129  10U-10-X-S4-SS  [C0402]  372.04 240.68 180 bottom
2C130  0.1U-25-X-S4-TY  [C0402]  428.99 127.92 90 bottom
2C131  22U-10-T-SA  [CODE_A]  434.54 130.48 0 bottom
2C132  22U-10-T-SA  [CODE_A]  434.54 125.35 0 top
2C133  22U-10-T-SA  [CODE_A]  434.54 127.92 0 top
2C134  22U-10-T-SA  [CODE_A]  434.54 127.92 0 bottom
2C135  22U-10-T-SA  [CODE_A]  434.54 125.35 0 bottom
2C136  10U-10-X-S4-SS  [C0402]  386.61 267.74 90 bottom
2C137  0.1U-25-X-S4-TY  [C0402]  385.5 267.74 90 bottom
2C138  NC/10U-10-X-S4-SS  [C0402]  387.73 267.74 90 bottom
2C139  22U-25-X-S8-MU  [C0805]  375.27 267.42 270 bottom
2C140  47U-16-T-SC  [CODE_C]  440.2 282.6 90 bottom
2C141  10U-16-T-SA  [CODE_A]  440.2 282.6 90 top
2C142  22U-25-X-S8-MU  [C0805]  377.56 267.42 270 bottom
2C143  NC/10P-50-N-S4-WA  [C0402]  395.78 250.66 180 bottom
2C144  NC/10P-50-N-S4-WA  [C0402]  395.78 249.49 180 bottom
2C145  NC/10P-50-N-S4-WA  [C0402]  528.27 268.08 270 top
2C146  NC/10P-50-N-S4-WA  [C0402]  528.27 264.88 270 top
2C147  NC/10P-50-N-S4-WA  [C0402]  528.27 275.35 270 top
2C148  NC/10P-50-N-S4-WA  [C0402]  528.27 272.15 270 top
2C149  NC/10P-50-N-S4-WA  [C0402]  528.27 259.45 270 top
2C150  NC/10P-50-N-S4-WA  [C0402]  528.27 256.25 270 top
2C152  0.1U-35-X-S2-MU  [C0201]  388.44 251.27 270 bottom
2C153  CNC-S2  [C0201]  390.9 247.1 180 bottom
2D1  RCLAMP3321P-SLP1006P2  [DIODE_1X0P6MM]  392.51 232.17 30 top
2D2  RCLAMP3321P-SLP1006P2  [DIODE_1X0P6MM]  389.02 228.35 0 top
2D3  RCLAMP3321P-SLP1006P2  [DIODE_1X0P6MM]  384 227.38 180 top
2J1  HDR-4X1-F-1  [CONN_4X1_2P54MM_FL10P5MM]  520.85 251.72 90 top
2J2  HDR-4X1-F-1  [CONN_4X1_2P54MM_FL10P5MM]  423.59 125.38 270 top
2J3  HDR-4X1-F-1  [CONN_4X1_2P54MM_FL10P5MM]  527.07 251.72 90 top
2J4  HDR-8X1-M  [JP_8P_100]  501.44 183.43 270 top
2J5  HDR-1X1-M  [JP_1P_RD070_040]  438.51 133.26 90 top
2J6  HDR-2X1-M  [JP_2P_100]  435.6 133.26 90 top
2J7  HDR-2X1-M  [JP_2P_100]  504.98 157.26 0 top
2J8  HDR-2X1-M  [JP_2P_100]  508.79 157.26 0 top
2J9  HDR-2X1-M  [JP_2P_100]  501.17 157.26 0 top
2K1  CU/UA2-12NJ-A-V2  [RL_NECUA2_12V_V2]  462.05 256.52 180 bottom
2K2  CU/UA2-12NJ-A-V2  [RL_NECUA2_12V_V2]  462.05 263.53 180 bottom
2K3  CU/UA2-12NJ-A-V2  [RL_NECUA2_12V_V2]  462.05 270.54 180 bottom
2K4  CU/UA2-12NJ-A-V2  [RL_NECUA2_12V_V2]  510.97 248.67 180 bottom
2K5  CU/UA2-12NJ-A-V2  [RL_NECUA2_12V_V2]  404.28 270.8 270 bottom
2K6  CU/UA2-12NJ-A-V2  [RL_NECUA2_12V_V2]  432.31 141.08 90 bottom
2K7  CU/UA2-12NJ-A-V2  [RL_NECUA2_12V_V2]  461.74 247.02 90 bottom
2K8  CU/UA2-12NJ-A-V2  [RL_NECUA2_12V_V2]  510.97 257.07 180 bottom
2K9  CU/UA2-12NJ-A-V2  [RL_NECUA2_12V_V2]  408.52 223.36 180 bottom
2K10  CU/UA2-12NJ-A-V2  [RL_NECUA2_12V_V2]  485.14 265.71 180 bottom
2K11  CU/UA2-12NJ-A-V2  [RL_NECUA2_12V_V2]  510.97 272.97 180 bottom
2K12  CU/UA2-12NJ-A-V2  [RL_NECUA2_12V_V2]  499.54 265.71 180 bottom
2K13  CU/UA2-12NJ-A-V2  [RL_NECUA2_12V_V2]  510.97 265.71 180 bottom
2K14  CU/UA2-12NJ-A-V2  [RL_NECUA2_12V_V2]  485.14 272.97 180 bottom
2K15  CU/UA2-12NJ-A-V2  [RL_NECUA2_12V_V2]  499.54 272.97 180 bottom
2K16  CU/UA2-12NJ-A-V2  [RL_NECUA2_12V_V2]  488.11 248.67 180 bottom
2K18  CU/UA2-12NJ-A-V2  [RL_NECUA2_12V_V2]  488.11 257.07 180 bottom
2K19  CU/UA2-12NJ-A-V2  [RL_NECUA2_12V_V2]  499.54 257.07 180 bottom
2K20  CU/UA2-12NJ-A-V2  [RL_NECUA2_12V_V2]  381.93 263.97 90 bottom
2K21  CU/UA2-12NJ-A-V2  [RL_NECUA2_12V_V2]  369.46 252.44 0 bottom
2K22  CU/UA2-12NJ-A-V2  [RL_NECUA2_12V_V2]  366.35 241.95 90 bottom
2K23  CU/UA2-12NJ-A-V2  [RL_NECUA2_12V_V2]  390.07 215.01 90 bottom
2K25  CU/UA2-12NJ-A-V2  [RL_NECUA2_12V_V2]  379.93 272.42 0 bottom
2K26  CU/UA2-12NJ-A-V2  [RL_NECUA2_12V_V2]  408.52 217 180 bottom
2K28  CU/UA2-12NJ-A-V2  [RL_NECUA2_12V_V2]  392.96 272.35 0 bottom
2K29  CU/UA2-12NJ-A-V2  [RL_NECUA2_12V_V2]  391.74 263.97 90 bottom
2K30  CU/UA2-12NJ-A-V2  [RL_NECUA2_12V_V2]  531.75 248.47 90 bottom
2K31  CU/UA2-12NJ-A-V2  [RL_NECUA2_12V_V2]  531.75 259.9 90 bottom
2K32  CU/UA2-12NJ-A-V2  [RL_NECUA2_12V_V2]  531.75 271.33 90 bottom
2K33  CU/UA2-12NJ-A-V2  [RL_NECUA2_12V_V2]  423.73 215 90 bottom
2K34  CU/UA2-12NJ-A-V2  [RL_NECUA2_12V_V2]  522.4 265.71 180 bottom
2K35  CU/UA2-12NJ-A-V2  [RL_NECUA2_12V_V2]  522.4 272.97 180 bottom
2K36  CU/UA2-12NJ-A-V2  [RL_NECUA2_12V_V2]  522.4 257.07 180 bottom
2K37  CU/UA2-12NJ-A-V2  [RL_NECUA2_12V_V2]  499.54 248.67 180 bottom
2K38  CU/UA2-12NJ-A-V2  [RL_NECUA2_12V_V2]  417.38 215 90 bottom
2K39  CU/UA2-12NJ-A-V2  [RL_NECUA2_12V_V2]  425.35 141.08 90 bottom
2L1  L2.2U-1.15A-S2.0X1.6-CT  [IND_201610]  370.75 247.9 270 bottom
2L3  L2.2U-1.15A-S2.0X1.6-CT  [IND_201610]  396.06 265.2 90 bottom
2L4  L2.2U-1.15A-S2.0X1.6-CT  [IND_201610]  386.25 265.2 90 bottom
2R1  0-5-S2  [R0201]  388.84 237.94 315 top
2R2  0-5-S2  [R0201]  387.06 237.2 315 top
2R3  0-5-S2  [R0201]  389.44 233.91 270 top
2R4  NC/0-5-S2  [R0201]  389.14 234.21 0 top
2R5  0-5-S2  [R0201]  385.35 236.59 270 bottom
2R6  0-5-S2  [R0201]  383.58 237.25 270 top
2R7  0-5-S2  [R0201]  383.58 229.9 270 top
2R8  NC/0-5-S2  [R0201]  383.88 230.2 180 top
2R9  0-5-S2  [R0201]  383.58 237.25 270 bottom
2R10  0-5-S4  [R0402]  471.79 272.44 270 top
2R11  0-5-S4  [R0402]  473.06 272.44 270 top
2R12  NC/10K-1-S4  [R0402]  475.7 253.02 270 top
2R13  0-5-S4  [R0402]  474.43 253.02 270 top
2R14  NC/10K-1-S4  [R0402]  474.33 272.44 270 top
2R15  0-5-S4  [R0402]  476.97 253.02 270 top
2R16  0-5-S4  [R0402]  475.6 272.44 270 top
2R17  0-5-S4  [R0402]  478.24 253.02 270 top
2R18  NC/10K-1-S4  [R0402]  476.71 272.44 270 top
2R19  0-5-S4  [R0402]  518.41 251.72 0 bottom
2R20  0-5-S4  [R0402]  518.41 246.64 0 bottom
2R21  0-5-S4  [R0402]  518.41 244.1 0 bottom
2R22  45.3-1-S4  [R0402]  399.07 272.79 90 bottom
2R23  45.3-1-S4  [R0402]  466.95 245.02 270 bottom
2R24  0-5-S4  [R0402]  426.18 125.4 180 bottom
2R25  45.3-1-S4  [R0402]  399.07 268.8 270 bottom
2R26  45.3-1-S4  [R0402]  466.95 249.01 90 bottom
2R27  0-5-S4  [R0402]  426.18 130.48 180 bottom
2R28  0-5-S4  [R0402]  426.18 133.02 180 bottom
2R29  NC/45.3-1-S4  [R0402]  488.83 252.91 270 bottom
2R30  0-5-S4  [R0402]  524.63 251.72 0 bottom
2R31  0-5-S4  [R0402]  524.63 246.64 0 bottom
2R32  0-5-S4  [R0402]  524.63 244.1 0 bottom
2R33  NC/45.3-1-S4  [R0402]  489.97 252.91 90 bottom
2R34  10K-1-S4  [R0402]  501.44 180.89 270 bottom
2R35  10K-1-S4  [R0402]  503.98 180.89 270 bottom
2R36  10K-1-S4  [R0402]  506.52 180.89 270 bottom
2R37  10K-1-S4  [R0402]  509.06 180.89 270 bottom
2R38  0-5-S4  [R0402]  503.86 170.73 0 bottom
2R39  10K-1-S4  [R0402]  511.6 180.89 270 bottom
2R40  10K-1-S4  [R0402]  514.14 180.89 270 bottom
2R41  10K-1-S4  [R0402]  516.68 180.89 270 bottom
2R42  0-5-S4  [R0402]  516.81 170.73 180 bottom
2R43  12K-1-S4  [R0402]  400.01 247.6 0 bottom
2R45  32.4-1-S4  [R0402]  491.38 266.92 270 bottom
2R47  32.4-1-S4  [R0402]  491.38 274.18 270 bottom
2R48  0-5-S4  [R0402]  362.74 238.45 90 bottom
2R49  NC/0-5-S4  [R0402]  369.96 238.45 90 bottom
2R50  0-5-S4  [R0402]  402.43 216.24 270 top
2R51  NC/0-5-S4  [R0402]  373.58 271.32 270 bottom
2R53  0-5-S4  [R0402]  386.61 274.45 90 bottom
2R54  NC/0-5-S4  [R0402]  386.61 270.25 270 bottom
2R55  0-5-S4  [R0402]  375.43 276.09 180 bottom
2R57  NC/10K-1-S4  [R0402]  512.27 252.3 180 bottom
2R58  NC/10K-1-S4  [R0402]  512.27 245.04 180 bottom
2R59  NC/10K-1-S4  [R0402]  512.27 260.71 180 bottom
2R60  NC/10K-1-S4  [R0402]  512.27 253.44 180 bottom
2R61  0-5-S4  [R0402]  411.78 124.98 0 bottom
2R62  0-5-S4  [R0402]  414.78 124.98 180 bottom
2R63  0-5-S4  [R0402]  493.7 274.18 270 bottom
2R64  0-5-S4  [R0402]  492.54 274.18 270 bottom
2R65  0-5-S4  [R0402]  492.54 271.76 90 bottom
2R66  0-5-S4  [R0402]  493.7 271.76 90 bottom
2R67  0-5-S4  [R0402]  493.7 266.92 270 bottom
2R68  0-5-S4  [R0402]  492.54 266.92 270 bottom
2R69  0-5-S4  [R0402]  492.54 264.5 90 bottom
2R70  0-5-S4  [R0402]  493.7 264.5 90 bottom
2R71  2-5-D-2  [RC02W_27MM]  548.2 246.67 0 bottom
2R72  2-5-D-2  [RC02W_27MM]  548.2 258.1 0 bottom
2R73  2-5-D-2  [RC02W_27MM]  548.2 269.53 0 bottom
2R74  0-5-S4  [R0402]  491.38 271.76 90 bottom
2R75  0-5-S4  [R0402]  491.38 264.5 90 bottom
2R76  0-5-S4  [R0402]  400.01 243.24 180 bottom
2R77  0-5-S4  [R0402]  395.77 252.13 180 bottom
2R78  0-5-S4  [R0402]  388.92 257.13 270 bottom
2R79  0-5-S4  [R0402]  383.37 257.13 270 bottom
2R81  0-5-S4  [R0402]  400.01 245.38 180 bottom
2R82  0-5-S4  [R0402]  400.01 248.7 180 bottom
2R83  0-5-S4  [R0402]  400.01 246.5 180 bottom
2SMP1  MINI-SMP-18S107-40ML5-V2  [CONN_SMP_18S107]  394.76 229.13 210 top
2SMP2  MINI-SMP-18S107-40ML5-V2  [CONN_SMP_18S107]  389.44 224.03 180 top
2SMP3  MINI-SMP-18S107-40ML5-V2  [CONN_SMP_18S107]  383.58 223.07 180 top
2ST3  SHORT  [DEFAULT_SHORT_SMALL]  365.63 260.48 270 top
2ST4  SHORT  [DEFAULT_SHORT_SMALL]  399.81 218.51 180 top
2ST5  SHORT  [DEFAULT_SHORT_SMALL]  399.81 217.75 180 top
2ST8  SHORT  [DEFAULT_SHORT_SMALL]  416.13 207.72 135 bottom
2ST11  SHORT  [DEFAULT_SHORT_SMALL]  386.74 265.51 270 top
2ST12  SHORT  [DEFAULT_SHORT_SMALL]  376.86 268.2 270 bottom
2ST13  SHORT  [DEFAULT_SHORT_SMALL]  362.74 240.69 270 bottom
2ST14  SHORT  [DEFAULT_SHORT_SMALL]  376.63 277.12 0 bottom
2ST15  SHORT  [DEFAULT_SHORT_SMALL]  401.74 244.4 270 bottom
2ST16  SHORT  [DEFAULT_SHORT_SMALL]  364.51 260.38 270 top
2ST17  SHORT  [DEFAULT_SHORT_SMALL]  376.04 268.22 270 bottom
2ST18  SHORT  [DEFAULT_SHORT_SMALL]  416.94 208.21 135 bottom
2ST19  SHORT  [DEFAULT_SHORT_SMALL]  385.77 265.56 270 top
2SW5  SW-SLIDE-8-D2.54-TRI-ECE  [SW_DIPX8P_2P54_MM_V2]  510.33 174.54 0 top
2SW6  SW-SLIDE-4-D2.54-TRI-ECE  [SW_DIPX4P_2P54MM_ETD]  413.28 128.79 0 top
2U1  RFASWA358ATF0G  [RF_SW_GW2159_6P]  387.66 233.75 270 top
2U2  RFASWA358ATF0G  [RF_SW_GW2159_6P]  385.36 229.74 270 top
2U3  MX25L25645GM2I-08G/SK-SO8-1.27  [SK_SO8_1P27MM_LOTES]  473.7 263.47 0 bottom
2Y1  XTAL40M-S2016-TAI-12P  [XTAL_2X1P6MM_4P_0P8MM]  373 243.89 45 top
3BD1  BD120-1.5A-S4-MU  [FB0402]  419.97 257.1 270 bottom
3BD2  BD120-1.5A-S4-MU  [FB0402]  435.74 254.24 180 bottom
3BD3  BD120-1.5A-S4-MU  [FB0402]  418.93 257.1 270 bottom
3BD5  BD120-1.5A-S4-MU  [FB0402]  416.11 247.53 0 bottom
3BD7  BD120-1.5A-S4-MU  [FB0402]  421.01 257.1 270 bottom
3BD9  BD120-1.5A-S4-MU  [FB0402]  439.98 244.31 180 bottom
3BD11  BD120-1.5A-S4-MU  [FB0402]  435.74 253.2 180 bottom
3BD12  BD120-1.5A-S4-MU  [FB0402]  427.85 257.1 270 bottom
3BD13  BD120-1.5A-S4-MU  [FB0402]  416.14 240.68 0 bottom
3BD15  BD120-1.5A-S4-MU  [FB0402]  419.26 236.89 0 bottom
3BD16  BD120-1.5A-S4-MU  [FB0402]  422.57 243.52 180 bottom
3BD17  BD120-1.5A-S4-MU  [FB0402]  422.57 242.48 180 bottom
3BD18  BD120-1.5A-S4-MU  [FB0402]  434.49 239.43 180 bottom
3BD19  BD120-1.5A-S4-MU  [FB0402]  434.49 238.23 180 bottom
3BD20  BD120-1.5A-S4-MU  [FB0402]  414.56 247.48 270 bottom
3BD21  BD120-1.5A-S4-MU  [FB0402]  434.49 236.09 180 bottom
3BD22  BD120-1.5A-S4-MU  [FB0402]  421.08 233.24 180 bottom
3BD23  BD120-1.5A-S4-MU  [FB0402]  421.08 235.3 0 bottom
3BD27  NC/BD120-1.5A-S4-MU  [FB0402]  491.65 219.12 0 bottom
3BD28  BD120-1.5A-S4-MU  [FB0402]  415.59 250.31 270 bottom
3BD29  BD120-1.5A-S4-MU  [FB0402]  425.59 257.1 270 bottom
3BD30  BD120-1.5A-S4-MU  [FB0402]  415.74 253.12 225 bottom
3BD31  BD120-1.5A-S4-MU  [FB0402]  432.63 256.63 180 bottom
3BD32  BD120-1.5A-S4-MU  [FB0402]  469.1 218.7 90 top
3BD33  BD120-1.5A-S4-MU  [FB0402]  468.47 127.89 270 bottom
3BD34  BD120-1.5A-S4-MU  [FB0402]  422.26 231.51 0 bottom
3BD35  BD120-1.5A-S4-MU  [FB0402]  432.4 236.09 180 bottom
3BD36  BD120-1.5A-S4-MU  [FB0402]  414.09 240.69 0 bottom
3BD37  BD120-1.5A-S4-MU  [FB0402]  429.98 257.1 270 bottom
3C1  NC/1P-25-N-S2-WA  [C0201]  427.94 238.42 45 top
3C2  10P-50-N-S2-MU  [C0201]  432.27 233.44 300 top
3C3  NC/1.2P-50-N-S2-MU  [C0201]  429.75 237.46 45 top
3C4  NC/1P-25-N-S2-WA  [C0201]  426.58 238.11 225 top
3C5  NC/1.2P-50-N-S2-MU  [C0201]  427.55 236.29 225 top
3C6  10P-50-N-S2-MU  [C0201]  429.44 232.63 90 top
3C7  NC/10P-50-N-S2-MU  [C0201]  429.14 232.33 180 top
3C8  CNC-S2  [C0201]  429.14 227.46 180 top
3C9  NC/1P-25-N-S2-WA  [C0201]  425.65 237.58 180 bottom
3C10  NC/1.2P-50-N-S2-MU  [C0201]  425.05 235.61 180 bottom
3C11  NC/1P-25-N-S2-WA  [C0201]  423.88 238.23 180 top
3C12  NC/1.2P-50-N-S2-MU  [C0201]  423.28 236.26 180 top
3C13  10P-50-N-S2-MU  [C0201]  423.58 228.62 90 top
3C14  NC/10P-50-N-S2-MU  [C0201]  423.88 228.32 0 top
3C15  CNC-S2  [C0201]  423.88 226.5 0 top
3C16  NC/1P-25-N-S2-WA  [C0201]  423.88 238.23 180 bottom
3C17  NC/0.1U-35-X-S2-MU  [C0201]  432.4 242.06 180 bottom
3C18  NC/0.1U-35-X-S2-MU  [C0201]  432.4 241.21 180 bottom
3C19  NC/1.2P-50-N-S2-MU  [C0201]  423.28 236.26 180 bottom
3C20  0.1U-35-X-S2-MU  [C0201]  432.4 238.98 0 bottom
3C21  0.1U-35-X-S2-MU  [C0201]  432.4 239.83 0 bottom
3C22  0.1U-16-X-S4-MU  [C0402]  471.64 218.73 270 top
3C23  0.9P-50-N-S4-MU  [C0402]  415.37 245.27 270 top
3C24  0.1U-25-X-S4-TY  [C0402]  491.61 218.04 180 bottom
3C25  0.9P-50-N-S4-MU  [C0402]  415.37 242.5 90 top
3C38  1P-50-N-S4-WA  [C0402]  499.64 226.42 180 bottom
3C39  22P-50-N-S4-AVX  [C0402]  503.04 226.42 180 bottom
3C40  1P-50-N-S4-WA  [C0402]  499.64 219.15 180 bottom
3C41  22P-50-N-S4-AVX  [C0402]  503.04 219.15 180 bottom
3C44  0.1U-35-X-S2-MU  [C0201]  422.71 247.36 0 bottom
3C45  0.1U-35-X-S2-MU  [C0201]  431.18 251.27 270 bottom
3C46  0.1U-35-X-S2-MU  [C0201]  422.71 246.51 0 bottom
3C47  0.1U-35-X-S2-MU  [C0201]  431.41 244.05 180 bottom
3C48  0.1U-35-X-S2-MU  [C0201]  418.55 244.6 180 top
3C49  0.1U-35-X-S2-MU  [C0201]  431.41 247.77 180 bottom
3C52  0.1U-35-X-S2-MU  [C0201]  422.71 248.21 0 bottom
3C53  10U-10-X-S4-SS  [C0402]  406.53 248.35 90 bottom
3C54  0.1U-35-X-S2-MU  [C0201]  427.6 251.27 270 bottom
3C55  0.1U-25-X-S4-TY  [C0402]  408.8 248.35 90 bottom
3C56  0.1U-35-X-S2-MU  [C0201]  435.52 245.28 0 top
3C57  NC/10U-10-X-S4-SS  [C0402]  407.66 248.35 90 bottom
3C58  0.1U-35-X-S2-MU  [C0201]  422.44 255.8 90 top
3C59  0.1U-35-X-S2-MU  [C0201]  431.4 249.26 180 bottom
3C60  10U-10-X-S4-SS  [C0402]  437.88 254.29 0 bottom
3C61  0.1U-35-X-S2-MU  [C0201]  426.65 251.26 270 bottom
3C62  22U-25-X-S8-MU  [C0805]  406.41 256.59 0 bottom
3C63  22U-25-X-S8-MU  [C0805]  406.41 258.62 0 bottom
3C64  0.1U-35-X-S2-MU  [C0201]  418.55 242.47 180 top
3C65  47U-16-T-SC  [CODE_C]  474.22 212.78 0 bottom
3C66  10U-16-T-SA  [CODE_A]  474.19 212.78 0 top
3C67  10U-10-X-S4-SS  [C0402]  437.88 253.17 0 bottom
3C68  22U-10-T-SA  [CODE_A]  437.27 210.88 0 bottom
3C69  22U-10-T-SA  [CODE_A]  437.27 213.47 0 bottom
3C70  22U-10-T-SA  [CODE_A]  437.27 216.04 0 bottom
3C71  22U-10-T-SA  [CODE_A]  437.27 213.47 0 top
3C72  22U-10-T-SA  [CODE_A]  437.27 210.88 0 top
3C73  10U-10-X-S4-SS  [C0402]  414.06 239.62 180 bottom
3C74  0.1U-35-X-S2-MU  [C0201]  425.35 242.65 90 bottom
3C75  0.1U-35-X-S2-MU  [C0201]  435.52 242.53 0 top
3C76  10U-10-X-S4-SS  [C0402]  419.23 237.96 180 bottom
3C77  0.1U-35-X-S2-MU  [C0201]  424.54 242.65 90 bottom
3C78  0.1U-35-X-S2-MU  [C0201]  418.55 243.15 180 top
3C79  0.1U-35-X-S2-MU  [C0201]  418.55 241.78 180 top
3C83  10U-10-X-S4-SS  [C0402]  434.52 240.52 0 bottom
3C84  0.1U-35-X-S2-MU  [C0201]  426.87 242.65 90 bottom
3C85  0.1U-35-X-S2-MU  [C0201]  426.14 242.65 90 bottom
3C88  0.1U-35-X-S2-MU  [C0201]  418.55 245.26 180 top
3C89  10U-10-X-S4-SS  [C0402]  413.03 248.85 180 bottom
3C90  10U-10-X-S4-SS  [C0402]  434.52 237.15 0 bottom
3C91  0.1U-35-X-S2-MU  [C0201]  426.46 239.87 0 bottom
3C92  22U-25-X-S8-MU  [C0805]  451.71 212.93 180 bottom
3C93  22U-25-X-S8-MU  [C0805]  451.71 212.93 180 top
3C94  47U-16-T-SC  [CODE_C]  451.13 209.62 180 bottom
3C95  10U-16-T-SA  [CODE_A]  451.13 209.62 180 top
3C96  10U-10-X-S4-SS  [C0402]  436.6 240.52 0 bottom
3C97  10U-10-X-S4-SS  [C0402]  420.61 232.74 270 top
3C98  0.1U-35-X-S2-MU  [C0201]  419.67 233.64 270 top
3C99  10U-10-X-S4-SS  [C0402]  421.55 234.8 270 top
3C100  0.1U-35-X-S2-MU  [C0201]  421.83 237.95 270 top
3C101  10U-10-X-S4-SS  [C0402]  413.03 247.01 180 bottom
3C102  0.1U-35-X-S2-MU  [C0201]  431.41 245.56 180 bottom
3C105  0.1U-35-X-S2-MU  [C0201]  431.4 246.35 180 bottom
3C106  10U-10-X-S4-SS  [C0402]  436.43 267.74 90 bottom
3C107  0.1U-35-X-S2-MU  [C0201]  435.52 246.65 0 top
3C108  0.1U-25-X-S4-TY  [C0402]  435.31 267.74 90 bottom
3C109  NC/10U-10-X-S4-SS  [C0402]  437.55 267.74 90 bottom
3C110  1U-10-X-S4-MU  [C0402]  437.14 242.53 180 top
3C111  10U-10-X-S4-SS  [C0402]  415.59 249.34 270 top
3C112  0.1U-35-X-S2-MU  [C0201]  417.6 250.06 270 top
3C113  10U-25-X-S6-MU  [C0603]  441.74 247.85 90 bottom
3C116  22U-25-X-S8-MU  [C0805]  426.8 259.97 180 bottom
3C117  22U-25-X-S8-MU  [C0805]  426.8 262.13 180 bottom
3C118  10U-10-X-S4-SS  [C0402]  424.5 257.13 90 bottom
3C119  0.1U-35-X-S2-MU  [C0201]  425.72 251.26 270 bottom
3C120  47U-16-T-SC  [CODE_C]  437.7 219.71 180 bottom
3C121  10U-16-T-SA  [CODE_A]  437.7 219.71 180 top
3C122  10U-10-X-S4-SS  [C0402]  436.6 239.41 0 bottom
3C123  10U-10-X-S4-SS  [C0402]  415.05 253.14 135 top
3C124  0.1U-35-X-S2-MU  [C0201]  418.55 251.94 180 top
3C125  10U-10-X-S4-SS  [C0402]  432.16 257.13 90 top
3C126  0.1U-35-X-S2-MU  [C0201]  432.11 255.75 180 top
3C127  10U-10-X-S4-SS  [C0402]  470.37 218.73 270 top
3C128  0.1U-35-X-S2-MU  [C0201]  472.91 218.73 270 top
3C129  10U-10-X-S4-SS  [C0402]  412.04 240.68 180 bottom
3C130  0.1U-25-X-S4-TY  [C0402]  467.38 127.92 90 bottom
3C131  22U-10-T-SA  [CODE_A]  472.92 130.48 0 bottom
3C132  22U-10-T-SA  [CODE_A]  472.92 125.35 0 top
3C133  22U-10-T-SA  [CODE_A]  472.92 127.92 0 top
3C134  22U-10-T-SA  [CODE_A]  472.92 127.92 0 bottom
3C135  22U-10-T-SA  [CODE_A]  472.92 125.35 0 bottom
3C136  10U-10-X-S4-SS  [C0402]  426.61 267.74 90 bottom
3C137  0.1U-25-X-S4-TY  [C0402]  425.5 267.74 90 bottom
3C138  NC/10U-10-X-S4-SS  [C0402]  427.73 267.74 90 bottom
3C139  22U-25-X-S8-MU  [C0805]  415.27 267.42 270 bottom
3C140  47U-16-T-SC  [CODE_C]  451.46 231.34 180 bottom
3C141  10U-16-T-SA  [CODE_A]  451.46 231.34 180 top
3C142  22U-25-X-S8-MU  [C0805]  417.56 267.42 270 bottom
3C143  NC/10P-50-N-S4-WA  [C0402]  435.78 250.66 180 bottom
3C144  NC/10P-50-N-S4-WA  [C0402]  435.78 249.49 180 bottom
3C145  NC/10P-50-N-S4-WA  [C0402]  528.27 233.79 270 top
3C146  NC/10P-50-N-S4-WA  [C0402]  528.27 230.59 270 top
3C147  NC/10P-50-N-S4-WA  [C0402]  528.27 241.06 270 top
3C148  NC/10P-50-N-S4-WA  [C0402]  528.27 237.86 270 top
3C149  NC/10P-50-N-S4-WA  [C0402]  528.27 225.16 270 top
3C150  NC/10P-50-N-S4-WA  [C0402]  528.27 221.96 270 top
3C152  0.1U-35-X-S2-MU  [C0201]  428.44 251.27 270 bottom
3C153  CNC-S2  [C0201]  430.9 247.1 180 bottom
3D1  RCLAMP3321P-SLP1006P2  [DIODE_1X0P6MM]  432.51 232.17 30 top
3D2  RCLAMP3321P-SLP1006P2  [DIODE_1X0P6MM]  429.02 228.35 0 top
3D3  RCLAMP3321P-SLP1006P2  [DIODE_1X0P6MM]  424 227.38 180 top
3J1  HDR-4X1-F-1  [CONN_4X1_2P54MM_FL10P5MM]  520.85 217.43 90 top
3J2  HDR-4X1-F-1  [CONN_4X1_2P54MM_FL10P5MM]  461.98 125.38 270 top
3J3  HDR-4X1-F-1  [CONN_4X1_2P54MM_FL10P5MM]  527.07 217.43 90 top
3J4  HDR-8X1-M  [JP_8P_100]  430.83 183.3 270 top
3J5  HDR-1X1-M  [JP_1P_RD070_040]  476.9 133.26 90 top
3J6  HDR-2X1-M  [JP_2P_100]  473.99 133.26 90 top
3J7  HDR-2X1-M  [JP_2P_100]  447.57 157.26 0 top
3J8  HDR-2X1-M  [JP_2P_100]  451.38 157.26 0 top
3J9  HDR-2X1-M  [JP_2P_100]  443.76 157.26 0 top
3K1  CU/UA2-12NJ-A-V2  [RL_NECUA2_12V_V2]  462.05 222.23 180 bottom
3K2  CU/UA2-12NJ-A-V2  [RL_NECUA2_12V_V2]  462.05 229.24 180 bottom
3K3  CU/UA2-12NJ-A-V2  [RL_NECUA2_12V_V2]  462.05 236.25 180 bottom
3K4  CU/UA2-12NJ-A-V2  [RL_NECUA2_12V_V2]  510.97 214.38 180 bottom
3K5  CU/UA2-12NJ-A-V2  [RL_NECUA2_12V_V2]  444.28 270.8 270 bottom
3K6  CU/UA2-12NJ-A-V2  [RL_NECUA2_12V_V2]  470.7 141.08 90 bottom
3K7  CU/UA2-12NJ-A-V2  [RL_NECUA2_12V_V2]  461.74 212.73 90 bottom
3K8  CU/UA2-12NJ-A-V2  [RL_NECUA2_12V_V2]  510.97 222.78 180 bottom
3K9  CU/UA2-12NJ-A-V2  [RL_NECUA2_12V_V2]  448.52 223.36 180 bottom
3K10  CU/UA2-12NJ-A-V2  [RL_NECUA2_12V_V2]  485.14 231.42 180 bottom
3K11  CU/UA2-12NJ-A-V2  [RL_NECUA2_12V_V2]  510.97 238.68 180 bottom
3K12  CU/UA2-12NJ-A-V2  [RL_NECUA2_12V_V2]  499.54 231.42 180 bottom
3K13  CU/UA2-12NJ-A-V2  [RL_NECUA2_12V_V2]  510.97 231.42 180 bottom
3K14  CU/UA2-12NJ-A-V2  [RL_NECUA2_12V_V2]  485.14 238.68 180 bottom
3K15  CU/UA2-12NJ-A-V2  [RL_NECUA2_12V_V2]  499.54 238.68 180 bottom
3K16  CU/UA2-12NJ-A-V2  [RL_NECUA2_12V_V2]  488.11 214.38 180 bottom
3K18  CU/UA2-12NJ-A-V2  [RL_NECUA2_12V_V2]  488.11 222.78 180 bottom
3K19  CU/UA2-12NJ-A-V2  [RL_NECUA2_12V_V2]  499.54 222.78 180 bottom
3K20  CU/UA2-12NJ-A-V2  [RL_NECUA2_12V_V2]  421.93 263.97 90 bottom
3K21  CU/UA2-12NJ-A-V2  [RL_NECUA2_12V_V2]  409.46 252.44 0 bottom
3K22  CU/UA2-12NJ-A-V2  [RL_NECUA2_12V_V2]  406.35 241.95 90 bottom
3K23  CU/UA2-12NJ-A-V2  [RL_NECUA2_12V_V2]  430.07 215.01 90 bottom
3K25  CU/UA2-12NJ-A-V2  [RL_NECUA2_12V_V2]  419.93 272.42 0 bottom
3K26  CU/UA2-12NJ-A-V2  [RL_NECUA2_12V_V2]  448.52 217 180 bottom
3K28  CU/UA2-12NJ-A-V2  [RL_NECUA2_12V_V2]  432.96 272.35 0 bottom
3K29  CU/UA2-12NJ-A-V2  [RL_NECUA2_12V_V2]  431.74 263.97 90 bottom
3K30  CU/UA2-12NJ-A-V2  [RL_NECUA2_12V_V2]  531.75 214.18 90 bottom
3K31  CU/UA2-12NJ-A-V2  [RL_NECUA2_12V_V2]  531.75 225.61 90 bottom
3K32  CU/UA2-12NJ-A-V2  [RL_NECUA2_12V_V2]  531.75 237.04 90 bottom
3K34  CU/UA2-12NJ-A-V2  [RL_NECUA2_12V_V2]  522.4 231.42 180 bottom
3K35  CU/UA2-12NJ-A-V2  [RL_NECUA2_12V_V2]  522.4 238.68 180 bottom
3K36  CU/UA2-12NJ-A-V2  [RL_NECUA2_12V_V2]  522.4 222.78 180 bottom
3K39  CU/UA2-12NJ-A-V2  [RL_NECUA2_12V_V2]  463.73 141.08 90 bottom
3L1  L2.2U-1.15A-S2.0X1.6-CT  [IND_201610]  410.75 247.9 270 bottom
3L3  L2.2U-1.15A-S2.0X1.6-CT  [IND_201610]  436.06 265.2 90 bottom
3L4  L2.2U-1.15A-S2.0X1.6-CT  [IND_201610]  426.25 265.2 90 bottom
3R1  0-5-S2  [R0201]  428.84 237.94 315 top
3R2  0-5-S2  [R0201]  427.06 237.2 315 top
3R3  0-5-S2  [R0201]  429.44 233.91 270 top
3R4  NC/0-5-S2  [R0201]  429.14 234.21 0 top
3R5  0-5-S2  [R0201]  425.35 236.59 270 bottom
3R6  0-5-S2  [R0201]  423.58 237.25 270 top
3R7  0-5-S2  [R0201]  423.58 229.9 270 top
3R8  NC/0-5-S2  [R0201]  423.88 230.2 180 top
3R9  0-5-S2  [R0201]  423.58 237.25 270 bottom
3R10  0-5-S4  [R0402]  471.79 238.15 270 top
3R11  0-5-S4  [R0402]  473.06 238.15 270 top
3R12  NC/10K-1-S4  [R0402]  475.7 218.73 270 top
3R13  0-5-S4  [R0402]  474.43 218.73 270 top
3R14  NC/10K-1-S4  [R0402]  474.33 238.15 270 top
3R15  0-5-S4  [R0402]  476.97 218.73 270 top
3R16  0-5-S4  [R0402]  475.6 238.15 270 top
3R17  0-5-S4  [R0402]  478.24 218.73 270 top
3R18  NC/10K-1-S4  [R0402]  476.71 238.15 270 top
3R19  0-5-S4  [R0402]  518.41 217.43 0 bottom
3R20  0-5-S4  [R0402]  518.41 212.35 0 bottom
3R21  0-5-S4  [R0402]  518.41 209.81 0 bottom
3R22  45.3-1-S4  [R0402]  439.07 272.79 90 bottom
3R23  45.3-1-S4  [R0402]  466.95 210.73 270 bottom
3R24  0-5-S4  [R0402]  464.57 125.4 180 bottom
3R25  45.3-1-S4  [R0402]  439.07 268.8 270 bottom
3R26  45.3-1-S4  [R0402]  466.95 214.72 90 bottom
3R27  0-5-S4  [R0402]  464.57 130.48 180 bottom
3R28  0-5-S4  [R0402]  464.57 133.02 180 bottom
3R29  NC/45.3-1-S4  [R0402]  488.83 218.62 270 bottom
3R30  0-5-S4  [R0402]  524.63 217.43 0 bottom
3R31  0-5-S4  [R0402]  524.63 212.35 0 bottom
3R32  0-5-S4  [R0402]  524.63 209.81 0 bottom
3R33  NC/45.3-1-S4  [R0402]  489.97 218.62 90 bottom
3R34  10K-1-S4  [R0402]  430.83 180.76 270 bottom
3R35  10K-1-S4  [R0402]  433.37 180.76 270 bottom
3R36  10K-1-S4  [R0402]  435.91 180.76 270 bottom
3R37  10K-1-S4  [R0402]  438.45 180.76 270 bottom
3R38  0-5-S4  [R0402]  433.25 170.6 0 bottom
3R39  10K-1-S4  [R0402]  440.99 180.76 270 bottom
3R40  10K-1-S4  [R0402]  443.53 180.76 270 bottom
3R41  10K-1-S4  [R0402]  446.07 180.76 270 bottom
3R42  0-5-S4  [R0402]  446.2 170.6 180 bottom
3R43  12K-1-S4  [R0402]  440.01 247.6 0 bottom
3R45  32.4-1-S4  [R0402]  491.38 232.63 270 bottom
3R47  32.4-1-S4  [R0402]  491.38 239.89 270 bottom
3R48  0-5-S4  [R0402]  402.74 238.45 90 bottom
3R49  NC/0-5-S4  [R0402]  409.96 238.45 90 bottom
3R50  0-5-S4  [R0402]  442.43 216.24 270 top
3R51  NC/0-5-S4  [R0402]  413.58 271.32 270 bottom
3R53  0-5-S4  [R0402]  426.61 274.45 90 bottom
3R54  NC/0-5-S4  [R0402]  426.61 270.25 270 bottom
3R55  0-5-S4  [R0402]  415.43 276.09 180 bottom
3R57  NC/10K-1-S4  [R0402]  512.27 218.01 180 bottom
3R58  NC/10K-1-S4  [R0402]  512.27 210.75 180 bottom
3R59  NC/10K-1-S4  [R0402]  512.27 226.42 180 bottom
3R60  NC/10K-1-S4  [R0402]  512.27 219.15 180 bottom
3R61  0-5-S4  [R0402]  450.17 124.98 0 bottom
3R62  0-5-S4  [R0402]  453.17 124.98 180 bottom
3R63  0-5-S4  [R0402]  493.7 239.89 270 bottom
3R64  0-5-S4  [R0402]  492.54 239.89 270 bottom
3R65  0-5-S4  [R0402]  492.54 237.47 90 bottom
3R66  0-5-S4  [R0402]  493.7 237.47 90 bottom
3R67  0-5-S4  [R0402]  493.7 232.63 270 bottom
3R68  0-5-S4  [R0402]  492.54 232.63 270 bottom
3R69  0-5-S4  [R0402]  492.54 230.21 90 bottom
3R70  0-5-S4  [R0402]  493.7 230.21 90 bottom
3R71  2-5-D-2  [RC02W_27MM]  548.2 212.38 0 bottom
3R72  2-5-D-2  [RC02W_27MM]  548.2 223.81 0 bottom
3R73  2-5-D-2  [RC02W_27MM]  548.2 235.24 0 bottom
3R74  0-5-S4  [R0402]  491.38 237.47 90 bottom
3R75  0-5-S4  [R0402]  491.38 230.21 90 bottom
3R76  0-5-S4  [R0402]  440.01 243.24 180 bottom
3R77  0-5-S4  [R0402]  435.77 252.13 180 bottom
3R78  0-5-S4  [R0402]  428.92 257.13 270 bottom
3R79  0-5-S4  [R0402]  423.37 257.13 270 bottom
3R81  0-5-S4  [R0402]  440.01 245.38 180 bottom
3R82  0-5-S4  [R0402]  440.01 248.7 180 bottom
3R83  0-5-S4  [R0402]  440.01 246.5 180 bottom
3SMP1  MINI-SMP-18S107-40ML5-V2  [CONN_SMP_18S107]  434.76 229.13 210 top
